VERSION 5.8 ;
BUSBITCHARS "[]" ;
DIVIDERCHAR "/" ;
UNITS
    DATABASE MICRONS 1000 ;
END UNITS

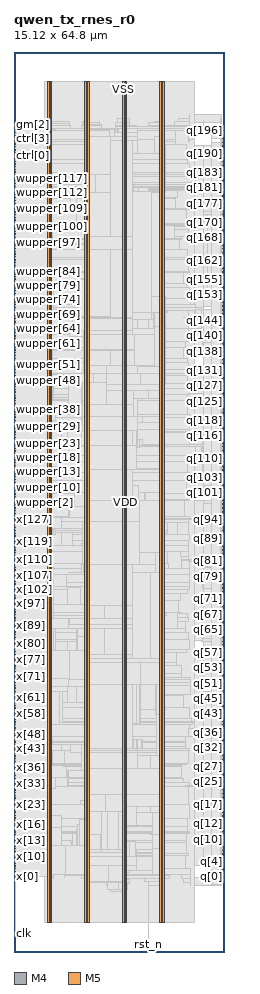
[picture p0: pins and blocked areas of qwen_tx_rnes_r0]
MACRO qwen_tx_rnes_r0
  FOREIGN qwen_tx_rnes_r0 0 0 ;
  CLASS BLOCK ;
  SIZE 15.12 BY 64.8 ;
  PIN clk
    DIRECTION INPUT ;
    USE SIGNAL ;
    PORT
      LAYER M4 ;
        RECT  0.054 1.296 0.138 1.32 ;
    END
    PORT
      LAYER M4 ;
        RECT  0.108 1.296 0.227 1.416 ;
    END
  END clk
  PIN ctrl[0]
    DIRECTION INPUT ;
    USE SIGNAL ;
    PORT
      LAYER M4 ;
        RECT  0.054 57.36 0.138 57.384 ;
    END
  END ctrl[0]
  PIN ctrl[1]
    DIRECTION INPUT ;
    USE SIGNAL ;
    PORT
      LAYER M4 ;
        RECT  0.054 57.552 0.138 57.576 ;
    END
  END ctrl[1]
  PIN ctrl[2]
    DIRECTION INPUT ;
    USE SIGNAL ;
    PORT
      LAYER M4 ;
        RECT  0.054 57.744 0.138 57.768 ;
    END
  END ctrl[2]
  PIN ctrl[3]
    DIRECTION INPUT ;
    USE SIGNAL ;
    PORT
      LAYER M4 ;
        RECT  0.054 57.984 0.138 58.008 ;
    END
  END ctrl[3]
  PIN ctrl[4]
    DIRECTION INPUT ;
    USE SIGNAL ;
    PORT
      LAYER M4 ;
        RECT  0.054 58.176 0.138 58.2 ;
    END
  END ctrl[4]
  PIN ctrl[5]
    DIRECTION INPUT ;
    USE SIGNAL ;
    PORT
      LAYER M4 ;
        RECT  0.054 58.368 0.138 58.392 ;
    END
  END ctrl[5]
  PIN gm[0]
    DIRECTION INPUT ;
    USE SIGNAL ;
    PORT
      LAYER M4 ;
        RECT  0.054 58.56 0.138 58.584 ;
    END
  END gm[0]
  PIN gm[1]
    DIRECTION INPUT ;
    USE SIGNAL ;
    PORT
      LAYER M4 ;
        RECT  0.054 58.8 0.138 58.824 ;
    END
  END gm[1]
  PIN gm[2]
    DIRECTION INPUT ;
    USE SIGNAL ;
    PORT
      LAYER M4 ;
        RECT  0.054 58.992 0.138 59.016 ;
    END
  END gm[2]
  PIN gm[3]
    DIRECTION INPUT ;
    USE SIGNAL ;
    PORT
      LAYER M4 ;
        RECT  0.054 59.184 0.138 59.208 ;
    END
  END gm[3]
  PIN q[0]
    DIRECTION OUTPUT ;
    USE SIGNAL ;
    PORT
      LAYER M4 ;
        RECT  14.982 5.424 15.066 5.448 ;
    END
  END q[0]
  PIN q[100]
    DIRECTION OUTPUT ;
    USE SIGNAL ;
    PORT
      LAYER M4 ;
        RECT  14.982 32.784 15.066 32.808 ;
    END
  END q[100]
  PIN q[101]
    DIRECTION OUTPUT ;
    USE SIGNAL ;
    PORT
      LAYER M4 ;
        RECT  14.982 33.072 15.066 33.096 ;
    END
  END q[101]
  PIN q[102]
    DIRECTION OUTPUT ;
    USE SIGNAL ;
    PORT
      LAYER M4 ;
        RECT  14.982 33.36 15.066 33.384 ;
    END
  END q[102]
  PIN q[103]
    DIRECTION OUTPUT ;
    USE SIGNAL ;
    PORT
      LAYER M4 ;
        RECT  14.982 33.6 15.066 33.624 ;
    END
  END q[103]
  PIN q[104]
    DIRECTION OUTPUT ;
    USE SIGNAL ;
    PORT
      LAYER M4 ;
        RECT  14.982 33.888 15.066 33.912 ;
    END
  END q[104]
  PIN q[105]
    DIRECTION OUTPUT ;
    USE SIGNAL ;
    PORT
      LAYER M4 ;
        RECT  14.982 34.176 15.066 34.2 ;
    END
  END q[105]
  PIN q[106]
    DIRECTION OUTPUT ;
    USE SIGNAL ;
    PORT
      LAYER M4 ;
        RECT  14.982 34.464 15.066 34.488 ;
    END
  END q[106]
  PIN q[107]
    DIRECTION OUTPUT ;
    USE SIGNAL ;
    PORT
      LAYER M4 ;
        RECT  14.982 34.704 15.066 34.728 ;
    END
  END q[107]
  PIN q[108]
    DIRECTION OUTPUT ;
    USE SIGNAL ;
    PORT
      LAYER M4 ;
        RECT  14.982 34.992 15.066 35.016 ;
    END
  END q[108]
  PIN q[109]
    DIRECTION OUTPUT ;
    USE SIGNAL ;
    PORT
      LAYER M4 ;
        RECT  14.982 35.28 15.066 35.304 ;
    END
  END q[109]
  PIN q[10]
    DIRECTION OUTPUT ;
    USE SIGNAL ;
    PORT
      LAYER M4 ;
        RECT  14.982 8.112 15.066 8.136 ;
    END
  END q[10]
  PIN q[110]
    DIRECTION OUTPUT ;
    USE SIGNAL ;
    PORT
      LAYER M4 ;
        RECT  14.982 35.52 15.066 35.544 ;
    END
  END q[110]
  PIN q[111]
    DIRECTION OUTPUT ;
    USE SIGNAL ;
    PORT
      LAYER M4 ;
        RECT  14.982 35.808 15.066 35.832 ;
    END
  END q[111]
  PIN q[112]
    DIRECTION OUTPUT ;
    USE SIGNAL ;
    PORT
      LAYER M4 ;
        RECT  14.982 36.096 15.066 36.12 ;
    END
  END q[112]
  PIN q[113]
    DIRECTION OUTPUT ;
    USE SIGNAL ;
    PORT
      LAYER M4 ;
        RECT  14.982 36.384 15.066 36.408 ;
    END
  END q[113]
  PIN q[114]
    DIRECTION OUTPUT ;
    USE SIGNAL ;
    PORT
      LAYER M4 ;
        RECT  14.982 36.624 15.066 36.648 ;
    END
  END q[114]
  PIN q[115]
    DIRECTION OUTPUT ;
    USE SIGNAL ;
    PORT
      LAYER M4 ;
        RECT  14.982 36.912 15.066 36.936 ;
    END
  END q[115]
  PIN q[116]
    DIRECTION OUTPUT ;
    USE SIGNAL ;
    PORT
      LAYER M4 ;
        RECT  14.982 37.2 15.066 37.224 ;
    END
  END q[116]
  PIN q[117]
    DIRECTION OUTPUT ;
    USE SIGNAL ;
    PORT
      LAYER M4 ;
        RECT  14.982 37.44 15.066 37.464 ;
    END
  END q[117]
  PIN q[118]
    DIRECTION OUTPUT ;
    USE SIGNAL ;
    PORT
      LAYER M4 ;
        RECT  14.982 37.728 15.066 37.752 ;
    END
  END q[118]
  PIN q[119]
    DIRECTION OUTPUT ;
    USE SIGNAL ;
    PORT
      LAYER M4 ;
        RECT  14.982 38.016 15.066 38.04 ;
    END
  END q[119]
  PIN q[11]
    DIRECTION OUTPUT ;
    USE SIGNAL ;
    PORT
      LAYER M4 ;
        RECT  14.982 8.4 15.066 8.424 ;
    END
  END q[11]
  PIN q[120]
    DIRECTION OUTPUT ;
    USE SIGNAL ;
    PORT
      LAYER M4 ;
        RECT  14.982 38.304 15.066 38.328 ;
    END
  END q[120]
  PIN q[121]
    DIRECTION OUTPUT ;
    USE SIGNAL ;
    PORT
      LAYER M4 ;
        RECT  14.982 38.544 15.066 38.568 ;
    END
  END q[121]
  PIN q[122]
    DIRECTION OUTPUT ;
    USE SIGNAL ;
    PORT
      LAYER M4 ;
        RECT  14.982 38.832 15.066 38.856 ;
    END
  END q[122]
  PIN q[123]
    DIRECTION OUTPUT ;
    USE SIGNAL ;
    PORT
      LAYER M4 ;
        RECT  14.982 39.12 15.066 39.144 ;
    END
  END q[123]
  PIN q[124]
    DIRECTION OUTPUT ;
    USE SIGNAL ;
    PORT
      LAYER M4 ;
        RECT  14.982 39.36 15.066 39.384 ;
    END
  END q[124]
  PIN q[125]
    DIRECTION OUTPUT ;
    USE SIGNAL ;
    PORT
      LAYER M4 ;
        RECT  14.982 39.648 15.066 39.672 ;
    END
  END q[125]
  PIN q[126]
    DIRECTION OUTPUT ;
    USE SIGNAL ;
    PORT
      LAYER M4 ;
        RECT  14.982 39.936 15.066 39.96 ;
    END
  END q[126]
  PIN q[127]
    DIRECTION OUTPUT ;
    USE SIGNAL ;
    PORT
      LAYER M4 ;
        RECT  14.982 40.224 15.066 40.248 ;
    END
  END q[127]
  PIN q[128]
    DIRECTION OUTPUT ;
    USE SIGNAL ;
    PORT
      LAYER M4 ;
        RECT  14.982 40.464 15.066 40.488 ;
    END
  END q[128]
  PIN q[129]
    DIRECTION OUTPUT ;
    USE SIGNAL ;
    PORT
      LAYER M4 ;
        RECT  14.982 40.752 15.066 40.776 ;
    END
  END q[129]
  PIN q[12]
    DIRECTION OUTPUT ;
    USE SIGNAL ;
    PORT
      LAYER M4 ;
        RECT  14.982 8.688 15.066 8.712 ;
    END
  END q[12]
  PIN q[130]
    DIRECTION OUTPUT ;
    USE SIGNAL ;
    PORT
      LAYER M4 ;
        RECT  14.982 41.04 15.066 41.064 ;
    END
  END q[130]
  PIN q[131]
    DIRECTION OUTPUT ;
    USE SIGNAL ;
    PORT
      LAYER M4 ;
        RECT  14.982 41.28 15.066 41.304 ;
    END
  END q[131]
  PIN q[132]
    DIRECTION OUTPUT ;
    USE SIGNAL ;
    PORT
      LAYER M4 ;
        RECT  14.982 41.568 15.066 41.592 ;
    END
  END q[132]
  PIN q[133]
    DIRECTION OUTPUT ;
    USE SIGNAL ;
    PORT
      LAYER M4 ;
        RECT  14.982 41.856 15.066 41.88 ;
    END
  END q[133]
  PIN q[134]
    DIRECTION OUTPUT ;
    USE SIGNAL ;
    PORT
      LAYER M4 ;
        RECT  14.982 42.096 15.066 42.12 ;
    END
  END q[134]
  PIN q[135]
    DIRECTION OUTPUT ;
    USE SIGNAL ;
    PORT
      LAYER M4 ;
        RECT  14.982 42.384 15.066 42.408 ;
    END
  END q[135]
  PIN q[136]
    DIRECTION OUTPUT ;
    USE SIGNAL ;
    PORT
      LAYER M4 ;
        RECT  14.982 42.672 15.066 42.696 ;
    END
  END q[136]
  PIN q[137]
    DIRECTION OUTPUT ;
    USE SIGNAL ;
    PORT
      LAYER M4 ;
        RECT  14.982 42.96 15.066 42.984 ;
    END
  END q[137]
  PIN q[138]
    DIRECTION OUTPUT ;
    USE SIGNAL ;
    PORT
      LAYER M4 ;
        RECT  14.982 43.2 15.066 43.224 ;
    END
  END q[138]
  PIN q[139]
    DIRECTION OUTPUT ;
    USE SIGNAL ;
    PORT
      LAYER M4 ;
        RECT  14.982 43.488 15.066 43.512 ;
    END
  END q[139]
  PIN q[13]
    DIRECTION OUTPUT ;
    USE SIGNAL ;
    PORT
      LAYER M4 ;
        RECT  14.982 8.928 15.066 8.952 ;
    END
  END q[13]
  PIN q[140]
    DIRECTION OUTPUT ;
    USE SIGNAL ;
    PORT
      LAYER M4 ;
        RECT  14.982 43.776 15.066 43.8 ;
    END
  END q[140]
  PIN q[141]
    DIRECTION OUTPUT ;
    USE SIGNAL ;
    PORT
      LAYER M4 ;
        RECT  14.982 44.016 15.066 44.04 ;
    END
  END q[141]
  PIN q[142]
    DIRECTION OUTPUT ;
    USE SIGNAL ;
    PORT
      LAYER M4 ;
        RECT  14.982 44.304 15.066 44.328 ;
    END
  END q[142]
  PIN q[143]
    DIRECTION OUTPUT ;
    USE SIGNAL ;
    PORT
      LAYER M4 ;
        RECT  14.982 44.592 15.066 44.616 ;
    END
  END q[143]
  PIN q[144]
    DIRECTION OUTPUT ;
    USE SIGNAL ;
    PORT
      LAYER M4 ;
        RECT  14.982 44.88 15.066 44.904 ;
    END
  END q[144]
  PIN q[145]
    DIRECTION OUTPUT ;
    USE SIGNAL ;
    PORT
      LAYER M4 ;
        RECT  14.982 45.12 15.066 45.144 ;
    END
  END q[145]
  PIN q[146]
    DIRECTION OUTPUT ;
    USE SIGNAL ;
    PORT
      LAYER M4 ;
        RECT  14.982 45.408 15.066 45.432 ;
    END
  END q[146]
  PIN q[147]
    DIRECTION OUTPUT ;
    USE SIGNAL ;
    PORT
      LAYER M4 ;
        RECT  14.982 45.696 15.066 45.72 ;
    END
  END q[147]
  PIN q[148]
    DIRECTION OUTPUT ;
    USE SIGNAL ;
    PORT
      LAYER M4 ;
        RECT  14.982 45.936 15.066 45.96 ;
    END
  END q[148]
  PIN q[149]
    DIRECTION OUTPUT ;
    USE SIGNAL ;
    PORT
      LAYER M4 ;
        RECT  14.982 46.224 15.066 46.248 ;
    END
  END q[149]
  PIN q[14]
    DIRECTION OUTPUT ;
    USE SIGNAL ;
    PORT
      LAYER M4 ;
        RECT  14.982 9.216 15.066 9.24 ;
    END
  END q[14]
  PIN q[150]
    DIRECTION OUTPUT ;
    USE SIGNAL ;
    PORT
      LAYER M4 ;
        RECT  14.982 46.512 15.066 46.536 ;
    END
  END q[150]
  PIN q[151]
    DIRECTION OUTPUT ;
    USE SIGNAL ;
    PORT
      LAYER M4 ;
        RECT  14.982 46.8 15.066 46.824 ;
    END
  END q[151]
  PIN q[152]
    DIRECTION OUTPUT ;
    USE SIGNAL ;
    PORT
      LAYER M4 ;
        RECT  14.982 47.04 15.066 47.064 ;
    END
  END q[152]
  PIN q[153]
    DIRECTION OUTPUT ;
    USE SIGNAL ;
    PORT
      LAYER M4 ;
        RECT  14.982 47.328 15.066 47.352 ;
    END
  END q[153]
  PIN q[154]
    DIRECTION OUTPUT ;
    USE SIGNAL ;
    PORT
      LAYER M4 ;
        RECT  14.982 47.616 15.066 47.64 ;
    END
  END q[154]
  PIN q[155]
    DIRECTION OUTPUT ;
    USE SIGNAL ;
    PORT
      LAYER M4 ;
        RECT  14.982 47.856 15.066 47.88 ;
    END
  END q[155]
  PIN q[156]
    DIRECTION OUTPUT ;
    USE SIGNAL ;
    PORT
      LAYER M4 ;
        RECT  14.982 48.144 15.066 48.168 ;
    END
  END q[156]
  PIN q[157]
    DIRECTION OUTPUT ;
    USE SIGNAL ;
    PORT
      LAYER M4 ;
        RECT  14.982 48.432 15.066 48.456 ;
    END
  END q[157]
  PIN q[158]
    DIRECTION OUTPUT ;
    USE SIGNAL ;
    PORT
      LAYER M4 ;
        RECT  14.982 48.72 15.066 48.744 ;
    END
  END q[158]
  PIN q[159]
    DIRECTION OUTPUT ;
    USE SIGNAL ;
    PORT
      LAYER M4 ;
        RECT  14.982 48.96 15.066 48.984 ;
    END
  END q[159]
  PIN q[15]
    DIRECTION OUTPUT ;
    USE SIGNAL ;
    PORT
      LAYER M4 ;
        RECT  14.982 9.504 15.066 9.528 ;
    END
  END q[15]
  PIN q[160]
    DIRECTION OUTPUT ;
    USE SIGNAL ;
    PORT
      LAYER M4 ;
        RECT  14.982 49.248 15.066 49.272 ;
    END
  END q[160]
  PIN q[161]
    DIRECTION OUTPUT ;
    USE SIGNAL ;
    PORT
      LAYER M4 ;
        RECT  14.982 49.536 15.066 49.56 ;
    END
  END q[161]
  PIN q[162]
    DIRECTION OUTPUT ;
    USE SIGNAL ;
    PORT
      LAYER M4 ;
        RECT  14.982 49.776 15.066 49.8 ;
    END
  END q[162]
  PIN q[163]
    DIRECTION OUTPUT ;
    USE SIGNAL ;
    PORT
      LAYER M4 ;
        RECT  14.982 50.064 15.066 50.088 ;
    END
  END q[163]
  PIN q[164]
    DIRECTION OUTPUT ;
    USE SIGNAL ;
    PORT
      LAYER M4 ;
        RECT  14.982 50.352 15.066 50.376 ;
    END
  END q[164]
  PIN q[165]
    DIRECTION OUTPUT ;
    USE SIGNAL ;
    PORT
      LAYER M4 ;
        RECT  14.982 50.64 15.066 50.664 ;
    END
  END q[165]
  PIN q[166]
    DIRECTION OUTPUT ;
    USE SIGNAL ;
    PORT
      LAYER M4 ;
        RECT  14.982 50.88 15.066 50.904 ;
    END
  END q[166]
  PIN q[167]
    DIRECTION OUTPUT ;
    USE SIGNAL ;
    PORT
      LAYER M4 ;
        RECT  14.982 51.168 15.066 51.192 ;
    END
  END q[167]
  PIN q[168]
    DIRECTION OUTPUT ;
    USE SIGNAL ;
    PORT
      LAYER M4 ;
        RECT  14.982 51.456 15.066 51.48 ;
    END
  END q[168]
  PIN q[169]
    DIRECTION OUTPUT ;
    USE SIGNAL ;
    PORT
      LAYER M4 ;
        RECT  14.982 51.696 15.066 51.72 ;
    END
  END q[169]
  PIN q[16]
    DIRECTION OUTPUT ;
    USE SIGNAL ;
    PORT
      LAYER M4 ;
        RECT  14.982 9.792 15.066 9.816 ;
    END
  END q[16]
  PIN q[170]
    DIRECTION OUTPUT ;
    USE SIGNAL ;
    PORT
      LAYER M4 ;
        RECT  14.982 51.984 15.066 52.008 ;
    END
  END q[170]
  PIN q[171]
    DIRECTION OUTPUT ;
    USE SIGNAL ;
    PORT
      LAYER M4 ;
        RECT  14.982 52.272 15.066 52.296 ;
    END
  END q[171]
  PIN q[172]
    DIRECTION OUTPUT ;
    USE SIGNAL ;
    PORT
      LAYER M4 ;
        RECT  14.982 52.512 15.066 52.536 ;
    END
  END q[172]
  PIN q[173]
    DIRECTION OUTPUT ;
    USE SIGNAL ;
    PORT
      LAYER M4 ;
        RECT  14.982 52.8 15.066 52.824 ;
    END
  END q[173]
  PIN q[174]
    DIRECTION OUTPUT ;
    USE SIGNAL ;
    PORT
      LAYER M4 ;
        RECT  14.982 53.088 15.066 53.112 ;
    END
  END q[174]
  PIN q[175]
    DIRECTION OUTPUT ;
    USE SIGNAL ;
    PORT
      LAYER M4 ;
        RECT  14.982 53.376 15.066 53.4 ;
    END
  END q[175]
  PIN q[176]
    DIRECTION OUTPUT ;
    USE SIGNAL ;
    PORT
      LAYER M4 ;
        RECT  14.982 53.616 15.066 53.64 ;
    END
  END q[176]
  PIN q[177]
    DIRECTION OUTPUT ;
    USE SIGNAL ;
    PORT
      LAYER M4 ;
        RECT  14.982 53.904 15.066 53.928 ;
    END
  END q[177]
  PIN q[178]
    DIRECTION OUTPUT ;
    USE SIGNAL ;
    PORT
      LAYER M4 ;
        RECT  14.982 54.192 15.066 54.216 ;
    END
  END q[178]
  PIN q[179]
    DIRECTION OUTPUT ;
    USE SIGNAL ;
    PORT
      LAYER M4 ;
        RECT  14.982 54.432 15.066 54.456 ;
    END
  END q[179]
  PIN q[17]
    DIRECTION OUTPUT ;
    USE SIGNAL ;
    PORT
      LAYER M4 ;
        RECT  14.982 10.032 15.066 10.056 ;
    END
  END q[17]
  PIN q[180]
    DIRECTION OUTPUT ;
    USE SIGNAL ;
    PORT
      LAYER M4 ;
        RECT  14.982 54.72 15.066 54.744 ;
    END
  END q[180]
  PIN q[181]
    DIRECTION OUTPUT ;
    USE SIGNAL ;
    PORT
      LAYER M4 ;
        RECT  14.982 55.008 15.066 55.032 ;
    END
  END q[181]
  PIN q[182]
    DIRECTION OUTPUT ;
    USE SIGNAL ;
    PORT
      LAYER M4 ;
        RECT  14.982 55.296 15.066 55.32 ;
    END
  END q[182]
  PIN q[183]
    DIRECTION OUTPUT ;
    USE SIGNAL ;
    PORT
      LAYER M4 ;
        RECT  14.982 55.536 15.066 55.56 ;
    END
  END q[183]
  PIN q[184]
    DIRECTION OUTPUT ;
    USE SIGNAL ;
    PORT
      LAYER M4 ;
        RECT  14.982 55.824 15.066 55.848 ;
    END
  END q[184]
  PIN q[185]
    DIRECTION OUTPUT ;
    USE SIGNAL ;
    PORT
      LAYER M4 ;
        RECT  14.982 56.112 15.066 56.136 ;
    END
  END q[185]
  PIN q[186]
    DIRECTION OUTPUT ;
    USE SIGNAL ;
    PORT
      LAYER M4 ;
        RECT  14.982 56.352 15.066 56.376 ;
    END
  END q[186]
  PIN q[187]
    DIRECTION OUTPUT ;
    USE SIGNAL ;
    PORT
      LAYER M4 ;
        RECT  14.982 56.64 15.066 56.664 ;
    END
  END q[187]
  PIN q[188]
    DIRECTION OUTPUT ;
    USE SIGNAL ;
    PORT
      LAYER M4 ;
        RECT  14.982 56.928 15.066 56.952 ;
    END
  END q[188]
  PIN q[189]
    DIRECTION OUTPUT ;
    USE SIGNAL ;
    PORT
      LAYER M4 ;
        RECT  14.982 57.216 15.066 57.24 ;
    END
  END q[189]
  PIN q[18]
    DIRECTION OUTPUT ;
    USE SIGNAL ;
    PORT
      LAYER M4 ;
        RECT  14.982 10.32 15.066 10.344 ;
    END
  END q[18]
  PIN q[190]
    DIRECTION OUTPUT ;
    USE SIGNAL ;
    PORT
      LAYER M4 ;
        RECT  14.982 57.456 15.066 57.48 ;
    END
  END q[190]
  PIN q[191]
    DIRECTION OUTPUT ;
    USE SIGNAL ;
    PORT
      LAYER M4 ;
        RECT  14.982 57.744 15.066 57.768 ;
    END
  END q[191]
  PIN q[192]
    DIRECTION OUTPUT ;
    USE SIGNAL ;
    PORT
      LAYER M4 ;
        RECT  14.982 58.032 15.066 58.056 ;
    END
  END q[192]
  PIN q[193]
    DIRECTION OUTPUT ;
    USE SIGNAL ;
    PORT
      LAYER M4 ;
        RECT  14.982 58.272 15.066 58.296 ;
    END
  END q[193]
  PIN q[194]
    DIRECTION OUTPUT ;
    USE SIGNAL ;
    PORT
      LAYER M4 ;
        RECT  14.982 58.56 15.066 58.584 ;
    END
  END q[194]
  PIN q[195]
    DIRECTION OUTPUT ;
    USE SIGNAL ;
    PORT
      LAYER M4 ;
        RECT  14.982 58.848 15.066 58.872 ;
    END
  END q[195]
  PIN q[196]
    DIRECTION OUTPUT ;
    USE SIGNAL ;
    PORT
      LAYER M4 ;
        RECT  14.982 59.136 15.066 59.16 ;
    END
  END q[196]
  PIN q[197]
    DIRECTION OUTPUT ;
    USE SIGNAL ;
    PORT
      LAYER M4 ;
        RECT  14.982 59.376 15.066 59.4 ;
    END
  END q[197]
  PIN q[19]
    DIRECTION OUTPUT ;
    USE SIGNAL ;
    PORT
      LAYER M4 ;
        RECT  14.982 10.608 15.066 10.632 ;
    END
  END q[19]
  PIN q[1]
    DIRECTION OUTPUT ;
    USE SIGNAL ;
    PORT
      LAYER M4 ;
        RECT  14.982 5.664 15.066 5.688 ;
    END
  END q[1]
  PIN q[20]
    DIRECTION OUTPUT ;
    USE SIGNAL ;
    PORT
      LAYER M4 ;
        RECT  14.982 10.848 15.066 10.872 ;
    END
  END q[20]
  PIN q[21]
    DIRECTION OUTPUT ;
    USE SIGNAL ;
    PORT
      LAYER M4 ;
        RECT  14.982 11.136 15.066 11.16 ;
    END
  END q[21]
  PIN q[22]
    DIRECTION OUTPUT ;
    USE SIGNAL ;
    PORT
      LAYER M4 ;
        RECT  14.982 11.424 15.066 11.448 ;
    END
  END q[22]
  PIN q[23]
    DIRECTION OUTPUT ;
    USE SIGNAL ;
    PORT
      LAYER M4 ;
        RECT  14.982 11.712 15.066 11.736 ;
    END
  END q[23]
  PIN q[24]
    DIRECTION OUTPUT ;
    USE SIGNAL ;
    PORT
      LAYER M4 ;
        RECT  14.982 11.952 15.066 11.976 ;
    END
  END q[24]
  PIN q[25]
    DIRECTION OUTPUT ;
    USE SIGNAL ;
    PORT
      LAYER M4 ;
        RECT  14.982 12.24 15.066 12.264 ;
    END
  END q[25]
  PIN q[26]
    DIRECTION OUTPUT ;
    USE SIGNAL ;
    PORT
      LAYER M4 ;
        RECT  14.982 12.528 15.066 12.552 ;
    END
  END q[26]
  PIN q[27]
    DIRECTION OUTPUT ;
    USE SIGNAL ;
    PORT
      LAYER M4 ;
        RECT  14.982 12.768 15.066 12.792 ;
    END
  END q[27]
  PIN q[28]
    DIRECTION OUTPUT ;
    USE SIGNAL ;
    PORT
      LAYER M4 ;
        RECT  14.982 13.056 15.066 13.08 ;
    END
  END q[28]
  PIN q[29]
    DIRECTION OUTPUT ;
    USE SIGNAL ;
    PORT
      LAYER M4 ;
        RECT  14.982 13.344 15.066 13.368 ;
    END
  END q[29]
  PIN q[2]
    DIRECTION OUTPUT ;
    USE SIGNAL ;
    PORT
      LAYER M4 ;
        RECT  14.982 5.952 15.066 5.976 ;
    END
  END q[2]
  PIN q[30]
    DIRECTION OUTPUT ;
    USE SIGNAL ;
    PORT
      LAYER M4 ;
        RECT  14.982 13.632 15.066 13.656 ;
    END
  END q[30]
  PIN q[31]
    DIRECTION OUTPUT ;
    USE SIGNAL ;
    PORT
      LAYER M4 ;
        RECT  14.982 13.872 15.066 13.896 ;
    END
  END q[31]
  PIN q[32]
    DIRECTION OUTPUT ;
    USE SIGNAL ;
    PORT
      LAYER M4 ;
        RECT  14.982 14.16 15.066 14.184 ;
    END
  END q[32]
  PIN q[33]
    DIRECTION OUTPUT ;
    USE SIGNAL ;
    PORT
      LAYER M4 ;
        RECT  14.982 14.448 15.066 14.472 ;
    END
  END q[33]
  PIN q[34]
    DIRECTION OUTPUT ;
    USE SIGNAL ;
    PORT
      LAYER M4 ;
        RECT  14.982 14.688 15.066 14.712 ;
    END
  END q[34]
  PIN q[35]
    DIRECTION OUTPUT ;
    USE SIGNAL ;
    PORT
      LAYER M4 ;
        RECT  14.982 14.976 15.066 15 ;
    END
  END q[35]
  PIN q[36]
    DIRECTION OUTPUT ;
    USE SIGNAL ;
    PORT
      LAYER M4 ;
        RECT  14.982 15.264 15.066 15.288 ;
    END
  END q[36]
  PIN q[37]
    DIRECTION OUTPUT ;
    USE SIGNAL ;
    PORT
      LAYER M4 ;
        RECT  14.982 15.552 15.066 15.576 ;
    END
  END q[37]
  PIN q[38]
    DIRECTION OUTPUT ;
    USE SIGNAL ;
    PORT
      LAYER M4 ;
        RECT  14.982 15.792 15.066 15.816 ;
    END
  END q[38]
  PIN q[39]
    DIRECTION OUTPUT ;
    USE SIGNAL ;
    PORT
      LAYER M4 ;
        RECT  14.982 16.08 15.066 16.104 ;
    END
  END q[39]
  PIN q[3]
    DIRECTION OUTPUT ;
    USE SIGNAL ;
    PORT
      LAYER M4 ;
        RECT  14.982 6.192 15.066 6.216 ;
    END
  END q[3]
  PIN q[40]
    DIRECTION OUTPUT ;
    USE SIGNAL ;
    PORT
      LAYER M4 ;
        RECT  14.982 16.368 15.066 16.392 ;
    END
  END q[40]
  PIN q[41]
    DIRECTION OUTPUT ;
    USE SIGNAL ;
    PORT
      LAYER M4 ;
        RECT  14.982 16.608 15.066 16.632 ;
    END
  END q[41]
  PIN q[42]
    DIRECTION OUTPUT ;
    USE SIGNAL ;
    PORT
      LAYER M4 ;
        RECT  14.982 16.896 15.066 16.92 ;
    END
  END q[42]
  PIN q[43]
    DIRECTION OUTPUT ;
    USE SIGNAL ;
    PORT
      LAYER M4 ;
        RECT  14.982 17.184 15.066 17.208 ;
    END
  END q[43]
  PIN q[44]
    DIRECTION OUTPUT ;
    USE SIGNAL ;
    PORT
      LAYER M4 ;
        RECT  14.982 17.472 15.066 17.496 ;
    END
  END q[44]
  PIN q[45]
    DIRECTION OUTPUT ;
    USE SIGNAL ;
    PORT
      LAYER M4 ;
        RECT  14.982 17.712 15.066 17.736 ;
    END
  END q[45]
  PIN q[46]
    DIRECTION OUTPUT ;
    USE SIGNAL ;
    PORT
      LAYER M4 ;
        RECT  14.982 18 15.066 18.024 ;
    END
  END q[46]
  PIN q[47]
    DIRECTION OUTPUT ;
    USE SIGNAL ;
    PORT
      LAYER M4 ;
        RECT  14.982 18.288 15.066 18.312 ;
    END
  END q[47]
  PIN q[48]
    DIRECTION OUTPUT ;
    USE SIGNAL ;
    PORT
      LAYER M4 ;
        RECT  14.982 18.528 15.066 18.552 ;
    END
  END q[48]
  PIN q[49]
    DIRECTION OUTPUT ;
    USE SIGNAL ;
    PORT
      LAYER M4 ;
        RECT  14.982 18.816 15.066 18.84 ;
    END
  END q[49]
  PIN q[4]
    DIRECTION OUTPUT ;
    USE SIGNAL ;
    PORT
      LAYER M4 ;
        RECT  14.982 6.48 15.066 6.504 ;
    END
  END q[4]
  PIN q[50]
    DIRECTION OUTPUT ;
    USE SIGNAL ;
    PORT
      LAYER M4 ;
        RECT  14.982 19.104 15.066 19.128 ;
    END
  END q[50]
  PIN q[51]
    DIRECTION OUTPUT ;
    USE SIGNAL ;
    PORT
      LAYER M4 ;
        RECT  14.982 19.344 15.066 19.368 ;
    END
  END q[51]
  PIN q[52]
    DIRECTION OUTPUT ;
    USE SIGNAL ;
    PORT
      LAYER M4 ;
        RECT  14.982 19.632 15.066 19.656 ;
    END
  END q[52]
  PIN q[53]
    DIRECTION OUTPUT ;
    USE SIGNAL ;
    PORT
      LAYER M4 ;
        RECT  14.982 19.92 15.066 19.944 ;
    END
  END q[53]
  PIN q[54]
    DIRECTION OUTPUT ;
    USE SIGNAL ;
    PORT
      LAYER M4 ;
        RECT  14.982 20.208 15.066 20.232 ;
    END
  END q[54]
  PIN q[55]
    DIRECTION OUTPUT ;
    USE SIGNAL ;
    PORT
      LAYER M4 ;
        RECT  14.982 20.448 15.066 20.472 ;
    END
  END q[55]
  PIN q[56]
    DIRECTION OUTPUT ;
    USE SIGNAL ;
    PORT
      LAYER M4 ;
        RECT  14.982 20.736 15.066 20.76 ;
    END
  END q[56]
  PIN q[57]
    DIRECTION OUTPUT ;
    USE SIGNAL ;
    PORT
      LAYER M4 ;
        RECT  14.982 21.024 15.066 21.048 ;
    END
  END q[57]
  PIN q[58]
    DIRECTION OUTPUT ;
    USE SIGNAL ;
    PORT
      LAYER M4 ;
        RECT  14.982 21.264 15.066 21.288 ;
    END
  END q[58]
  PIN q[59]
    DIRECTION OUTPUT ;
    USE SIGNAL ;
    PORT
      LAYER M4 ;
        RECT  14.982 21.552 15.066 21.576 ;
    END
  END q[59]
  PIN q[5]
    DIRECTION OUTPUT ;
    USE SIGNAL ;
    PORT
      LAYER M4 ;
        RECT  14.982 6.768 15.066 6.792 ;
    END
  END q[5]
  PIN q[60]
    DIRECTION OUTPUT ;
    USE SIGNAL ;
    PORT
      LAYER M4 ;
        RECT  14.982 21.84 15.066 21.864 ;
    END
  END q[60]
  PIN q[61]
    DIRECTION OUTPUT ;
    USE SIGNAL ;
    PORT
      LAYER M4 ;
        RECT  14.982 22.128 15.066 22.152 ;
    END
  END q[61]
  PIN q[62]
    DIRECTION OUTPUT ;
    USE SIGNAL ;
    PORT
      LAYER M4 ;
        RECT  14.982 22.368 15.066 22.392 ;
    END
  END q[62]
  PIN q[63]
    DIRECTION OUTPUT ;
    USE SIGNAL ;
    PORT
      LAYER M4 ;
        RECT  14.982 22.656 15.066 22.68 ;
    END
  END q[63]
  PIN q[64]
    DIRECTION OUTPUT ;
    USE SIGNAL ;
    PORT
      LAYER M4 ;
        RECT  14.982 22.944 15.066 22.968 ;
    END
  END q[64]
  PIN q[65]
    DIRECTION OUTPUT ;
    USE SIGNAL ;
    PORT
      LAYER M4 ;
        RECT  14.982 23.184 15.066 23.208 ;
    END
  END q[65]
  PIN q[66]
    DIRECTION OUTPUT ;
    USE SIGNAL ;
    PORT
      LAYER M4 ;
        RECT  14.982 23.472 15.066 23.496 ;
    END
  END q[66]
  PIN q[67]
    DIRECTION OUTPUT ;
    USE SIGNAL ;
    PORT
      LAYER M4 ;
        RECT  14.982 23.76 15.066 23.784 ;
    END
  END q[67]
  PIN q[68]
    DIRECTION OUTPUT ;
    USE SIGNAL ;
    PORT
      LAYER M4 ;
        RECT  14.982 24.048 15.066 24.072 ;
    END
  END q[68]
  PIN q[69]
    DIRECTION OUTPUT ;
    USE SIGNAL ;
    PORT
      LAYER M4 ;
        RECT  14.982 24.288 15.066 24.312 ;
    END
  END q[69]
  PIN q[6]
    DIRECTION OUTPUT ;
    USE SIGNAL ;
    PORT
      LAYER M4 ;
        RECT  14.982 7.056 15.066 7.08 ;
    END
  END q[6]
  PIN q[70]
    DIRECTION OUTPUT ;
    USE SIGNAL ;
    PORT
      LAYER M4 ;
        RECT  14.982 24.576 15.066 24.6 ;
    END
  END q[70]
  PIN q[71]
    DIRECTION OUTPUT ;
    USE SIGNAL ;
    PORT
      LAYER M4 ;
        RECT  14.982 24.864 15.066 24.888 ;
    END
  END q[71]
  PIN q[72]
    DIRECTION OUTPUT ;
    USE SIGNAL ;
    PORT
      LAYER M4 ;
        RECT  14.982 25.104 15.066 25.128 ;
    END
  END q[72]
  PIN q[73]
    DIRECTION OUTPUT ;
    USE SIGNAL ;
    PORT
      LAYER M4 ;
        RECT  14.982 25.392 15.066 25.416 ;
    END
  END q[73]
  PIN q[74]
    DIRECTION OUTPUT ;
    USE SIGNAL ;
    PORT
      LAYER M4 ;
        RECT  14.982 25.68 15.066 25.704 ;
    END
  END q[74]
  PIN q[75]
    DIRECTION OUTPUT ;
    USE SIGNAL ;
    PORT
      LAYER M4 ;
        RECT  14.982 25.968 15.066 25.992 ;
    END
  END q[75]
  PIN q[76]
    DIRECTION OUTPUT ;
    USE SIGNAL ;
    PORT
      LAYER M4 ;
        RECT  14.982 26.208 15.066 26.232 ;
    END
  END q[76]
  PIN q[77]
    DIRECTION OUTPUT ;
    USE SIGNAL ;
    PORT
      LAYER M4 ;
        RECT  14.982 26.496 15.066 26.52 ;
    END
  END q[77]
  PIN q[78]
    DIRECTION OUTPUT ;
    USE SIGNAL ;
    PORT
      LAYER M4 ;
        RECT  14.982 26.784 15.066 26.808 ;
    END
  END q[78]
  PIN q[79]
    DIRECTION OUTPUT ;
    USE SIGNAL ;
    PORT
      LAYER M4 ;
        RECT  14.982 27.024 15.066 27.048 ;
    END
  END q[79]
  PIN q[7]
    DIRECTION OUTPUT ;
    USE SIGNAL ;
    PORT
      LAYER M4 ;
        RECT  14.982 7.296 15.066 7.32 ;
    END
  END q[7]
  PIN q[80]
    DIRECTION OUTPUT ;
    USE SIGNAL ;
    PORT
      LAYER M4 ;
        RECT  14.982 27.312 15.066 27.336 ;
    END
  END q[80]
  PIN q[81]
    DIRECTION OUTPUT ;
    USE SIGNAL ;
    PORT
      LAYER M4 ;
        RECT  14.982 27.6 15.066 27.624 ;
    END
  END q[81]
  PIN q[82]
    DIRECTION OUTPUT ;
    USE SIGNAL ;
    PORT
      LAYER M4 ;
        RECT  14.982 27.888 15.066 27.912 ;
    END
  END q[82]
  PIN q[83]
    DIRECTION OUTPUT ;
    USE SIGNAL ;
    PORT
      LAYER M4 ;
        RECT  14.982 28.128 15.066 28.152 ;
    END
  END q[83]
  PIN q[84]
    DIRECTION OUTPUT ;
    USE SIGNAL ;
    PORT
      LAYER M4 ;
        RECT  14.982 28.416 15.066 28.44 ;
    END
  END q[84]
  PIN q[85]
    DIRECTION OUTPUT ;
    USE SIGNAL ;
    PORT
      LAYER M4 ;
        RECT  14.982 28.704 15.066 28.728 ;
    END
  END q[85]
  PIN q[86]
    DIRECTION OUTPUT ;
    USE SIGNAL ;
    PORT
      LAYER M4 ;
        RECT  14.982 28.944 15.066 28.968 ;
    END
  END q[86]
  PIN q[87]
    DIRECTION OUTPUT ;
    USE SIGNAL ;
    PORT
      LAYER M4 ;
        RECT  14.982 29.232 15.066 29.256 ;
    END
  END q[87]
  PIN q[88]
    DIRECTION OUTPUT ;
    USE SIGNAL ;
    PORT
      LAYER M4 ;
        RECT  14.982 29.52 15.066 29.544 ;
    END
  END q[88]
  PIN q[89]
    DIRECTION OUTPUT ;
    USE SIGNAL ;
    PORT
      LAYER M4 ;
        RECT  14.982 29.76 15.066 29.784 ;
    END
  END q[89]
  PIN q[8]
    DIRECTION OUTPUT ;
    USE SIGNAL ;
    PORT
      LAYER M4 ;
        RECT  14.982 7.584 15.066 7.608 ;
    END
  END q[8]
  PIN q[90]
    DIRECTION OUTPUT ;
    USE SIGNAL ;
    PORT
      LAYER M4 ;
        RECT  14.982 30.048 15.066 30.072 ;
    END
  END q[90]
  PIN q[91]
    DIRECTION OUTPUT ;
    USE SIGNAL ;
    PORT
      LAYER M4 ;
        RECT  14.982 30.336 15.066 30.36 ;
    END
  END q[91]
  PIN q[92]
    DIRECTION OUTPUT ;
    USE SIGNAL ;
    PORT
      LAYER M4 ;
        RECT  14.982 30.624 15.066 30.648 ;
    END
  END q[92]
  PIN q[93]
    DIRECTION OUTPUT ;
    USE SIGNAL ;
    PORT
      LAYER M4 ;
        RECT  14.982 30.864 15.066 30.888 ;
    END
  END q[93]
  PIN q[94]
    DIRECTION OUTPUT ;
    USE SIGNAL ;
    PORT
      LAYER M4 ;
        RECT  14.982 31.152 15.066 31.176 ;
    END
  END q[94]
  PIN q[95]
    DIRECTION OUTPUT ;
    USE SIGNAL ;
    PORT
      LAYER M4 ;
        RECT  14.982 31.44 15.066 31.464 ;
    END
  END q[95]
  PIN q[96]
    DIRECTION OUTPUT ;
    USE SIGNAL ;
    PORT
      LAYER M4 ;
        RECT  14.982 31.68 15.066 31.704 ;
    END
  END q[96]
  PIN q[97]
    DIRECTION OUTPUT ;
    USE SIGNAL ;
    PORT
      LAYER M4 ;
        RECT  14.982 31.968 15.066 31.992 ;
    END
  END q[97]
  PIN q[98]
    DIRECTION OUTPUT ;
    USE SIGNAL ;
    PORT
      LAYER M4 ;
        RECT  14.982 32.256 15.066 32.28 ;
    END
  END q[98]
  PIN q[99]
    DIRECTION OUTPUT ;
    USE SIGNAL ;
    PORT
      LAYER M4 ;
        RECT  14.982 32.544 15.066 32.568 ;
    END
  END q[99]
  PIN q[9]
    DIRECTION OUTPUT ;
    USE SIGNAL ;
    PORT
      LAYER M4 ;
        RECT  14.982 7.872 15.066 7.896 ;
    END
  END q[9]
  PIN round
    DIRECTION INPUT ;
    USE SIGNAL ;
    PORT
      LAYER M4 ;
        RECT  0.054 59.376 0.138 59.4 ;
    END
  END round
  PIN rst_n
    DIRECTION INPUT ;
    USE SIGNAL ;
    PORT
      LAYER M5 ;
        RECT  9.696 0.054 9.72 0.138 ;
    END
    PORT
      LAYER M5 ;
        RECT  9.696 0.08 9.72 0.563 ;
    END
  END rst_n
  PIN wupper[0]
    DIRECTION INPUT ;
    USE SIGNAL ;
    PORT
      LAYER M4 ;
        RECT  0.054 31.392 0.138 31.416 ;
    END
  END wupper[0]
  PIN wupper[100]
    DIRECTION INPUT ;
    USE SIGNAL ;
    PORT
      LAYER M4 ;
        RECT  0.054 51.696 0.138 51.72 ;
    END
  END wupper[100]
  PIN wupper[101]
    DIRECTION INPUT ;
    USE SIGNAL ;
    PORT
      LAYER M4 ;
        RECT  0.054 51.888 0.138 51.912 ;
    END
  END wupper[101]
  PIN wupper[102]
    DIRECTION INPUT ;
    USE SIGNAL ;
    PORT
      LAYER M4 ;
        RECT  0.054 52.08 0.138 52.104 ;
    END
  END wupper[102]
  PIN wupper[103]
    DIRECTION INPUT ;
    USE SIGNAL ;
    PORT
      LAYER M4 ;
        RECT  0.054 52.272 0.138 52.296 ;
    END
  END wupper[103]
  PIN wupper[104]
    DIRECTION INPUT ;
    USE SIGNAL ;
    PORT
      LAYER M4 ;
        RECT  0.054 52.464 0.138 52.488 ;
    END
  END wupper[104]
  PIN wupper[105]
    DIRECTION INPUT ;
    USE SIGNAL ;
    PORT
      LAYER M4 ;
        RECT  0.054 52.704 0.138 52.728 ;
    END
  END wupper[105]
  PIN wupper[106]
    DIRECTION INPUT ;
    USE SIGNAL ;
    PORT
      LAYER M4 ;
        RECT  0.054 52.896 0.138 52.92 ;
    END
  END wupper[106]
  PIN wupper[107]
    DIRECTION INPUT ;
    USE SIGNAL ;
    PORT
      LAYER M4 ;
        RECT  0.054 53.088 0.138 53.112 ;
    END
  END wupper[107]
  PIN wupper[108]
    DIRECTION INPUT ;
    USE SIGNAL ;
    PORT
      LAYER M4 ;
        RECT  0.054 53.28 0.138 53.304 ;
    END
  END wupper[108]
  PIN wupper[109]
    DIRECTION INPUT ;
    USE SIGNAL ;
    PORT
      LAYER M4 ;
        RECT  0.054 53.52 0.138 53.544 ;
    END
  END wupper[109]
  PIN wupper[10]
    DIRECTION INPUT ;
    USE SIGNAL ;
    PORT
      LAYER M4 ;
        RECT  0.054 33.408 0.138 33.432 ;
    END
  END wupper[10]
  PIN wupper[110]
    DIRECTION INPUT ;
    USE SIGNAL ;
    PORT
      LAYER M4 ;
        RECT  0.054 53.712 0.138 53.736 ;
    END
  END wupper[110]
  PIN wupper[111]
    DIRECTION INPUT ;
    USE SIGNAL ;
    PORT
      LAYER M4 ;
        RECT  0.054 53.904 0.138 53.928 ;
    END
  END wupper[111]
  PIN wupper[112]
    DIRECTION INPUT ;
    USE SIGNAL ;
    PORT
      LAYER M4 ;
        RECT  0.054 54.096 0.138 54.12 ;
    END
  END wupper[112]
  PIN wupper[113]
    DIRECTION INPUT ;
    USE SIGNAL ;
    PORT
      LAYER M4 ;
        RECT  0.054 54.336 0.138 54.36 ;
    END
  END wupper[113]
  PIN wupper[114]
    DIRECTION INPUT ;
    USE SIGNAL ;
    PORT
      LAYER M4 ;
        RECT  0.054 54.528 0.138 54.552 ;
    END
  END wupper[114]
  PIN wupper[115]
    DIRECTION INPUT ;
    USE SIGNAL ;
    PORT
      LAYER M4 ;
        RECT  0.054 54.72 0.138 54.744 ;
    END
  END wupper[115]
  PIN wupper[116]
    DIRECTION INPUT ;
    USE SIGNAL ;
    PORT
      LAYER M4 ;
        RECT  0.054 54.912 0.138 54.936 ;
    END
  END wupper[116]
  PIN wupper[117]
    DIRECTION INPUT ;
    USE SIGNAL ;
    PORT
      LAYER M4 ;
        RECT  0.054 55.104 0.138 55.128 ;
    END
  END wupper[117]
  PIN wupper[118]
    DIRECTION INPUT ;
    USE SIGNAL ;
    PORT
      LAYER M4 ;
        RECT  0.054 55.344 0.138 55.368 ;
    END
  END wupper[118]
  PIN wupper[119]
    DIRECTION INPUT ;
    USE SIGNAL ;
    PORT
      LAYER M4 ;
        RECT  0.054 55.536 0.138 55.56 ;
    END
  END wupper[119]
  PIN wupper[11]
    DIRECTION INPUT ;
    USE SIGNAL ;
    PORT
      LAYER M4 ;
        RECT  0.054 33.6 0.138 33.624 ;
    END
  END wupper[11]
  PIN wupper[120]
    DIRECTION INPUT ;
    USE SIGNAL ;
    PORT
      LAYER M4 ;
        RECT  0.054 55.728 0.138 55.752 ;
    END
  END wupper[120]
  PIN wupper[121]
    DIRECTION INPUT ;
    USE SIGNAL ;
    PORT
      LAYER M4 ;
        RECT  0.054 55.92 0.138 55.944 ;
    END
  END wupper[121]
  PIN wupper[122]
    DIRECTION INPUT ;
    USE SIGNAL ;
    PORT
      LAYER M4 ;
        RECT  0.054 56.16 0.138 56.184 ;
    END
  END wupper[122]
  PIN wupper[123]
    DIRECTION INPUT ;
    USE SIGNAL ;
    PORT
      LAYER M4 ;
        RECT  0.054 56.352 0.138 56.376 ;
    END
  END wupper[123]
  PIN wupper[124]
    DIRECTION INPUT ;
    USE SIGNAL ;
    PORT
      LAYER M4 ;
        RECT  0.054 56.544 0.138 56.568 ;
    END
  END wupper[124]
  PIN wupper[125]
    DIRECTION INPUT ;
    USE SIGNAL ;
    PORT
      LAYER M4 ;
        RECT  0.054 56.736 0.138 56.76 ;
    END
  END wupper[125]
  PIN wupper[126]
    DIRECTION INPUT ;
    USE SIGNAL ;
    PORT
      LAYER M4 ;
        RECT  0.054 56.928 0.138 56.952 ;
    END
  END wupper[126]
  PIN wupper[127]
    DIRECTION INPUT ;
    USE SIGNAL ;
    PORT
      LAYER M4 ;
        RECT  0.054 57.168 0.138 57.192 ;
    END
  END wupper[127]
  PIN wupper[12]
    DIRECTION INPUT ;
    USE SIGNAL ;
    PORT
      LAYER M4 ;
        RECT  0.054 33.792 0.138 33.816 ;
    END
  END wupper[12]
  PIN wupper[13]
    DIRECTION INPUT ;
    USE SIGNAL ;
    PORT
      LAYER M4 ;
        RECT  0.054 34.032 0.138 34.056 ;
    END
  END wupper[13]
  PIN wupper[14]
    DIRECTION INPUT ;
    USE SIGNAL ;
    PORT
      LAYER M4 ;
        RECT  0.054 34.224 0.138 34.248 ;
    END
  END wupper[14]
  PIN wupper[15]
    DIRECTION INPUT ;
    USE SIGNAL ;
    PORT
      LAYER M4 ;
        RECT  0.054 34.416 0.138 34.44 ;
    END
  END wupper[15]
  PIN wupper[16]
    DIRECTION INPUT ;
    USE SIGNAL ;
    PORT
      LAYER M4 ;
        RECT  0.054 34.608 0.138 34.632 ;
    END
  END wupper[16]
  PIN wupper[17]
    DIRECTION INPUT ;
    USE SIGNAL ;
    PORT
      LAYER M4 ;
        RECT  0.054 34.848 0.138 34.872 ;
    END
  END wupper[17]
  PIN wupper[18]
    DIRECTION INPUT ;
    USE SIGNAL ;
    PORT
      LAYER M4 ;
        RECT  0.054 35.04 0.138 35.064 ;
    END
  END wupper[18]
  PIN wupper[19]
    DIRECTION INPUT ;
    USE SIGNAL ;
    PORT
      LAYER M4 ;
        RECT  0.054 35.232 0.138 35.256 ;
    END
  END wupper[19]
  PIN wupper[1]
    DIRECTION INPUT ;
    USE SIGNAL ;
    PORT
      LAYER M4 ;
        RECT  0.054 31.584 0.138 31.608 ;
    END
  END wupper[1]
  PIN wupper[20]
    DIRECTION INPUT ;
    USE SIGNAL ;
    PORT
      LAYER M4 ;
        RECT  0.054 35.424 0.138 35.448 ;
    END
  END wupper[20]
  PIN wupper[21]
    DIRECTION INPUT ;
    USE SIGNAL ;
    PORT
      LAYER M4 ;
        RECT  0.054 35.616 0.138 35.64 ;
    END
  END wupper[21]
  PIN wupper[22]
    DIRECTION INPUT ;
    USE SIGNAL ;
    PORT
      LAYER M4 ;
        RECT  0.054 35.856 0.138 35.88 ;
    END
  END wupper[22]
  PIN wupper[23]
    DIRECTION INPUT ;
    USE SIGNAL ;
    PORT
      LAYER M4 ;
        RECT  0.054 36.048 0.138 36.072 ;
    END
  END wupper[23]
  PIN wupper[24]
    DIRECTION INPUT ;
    USE SIGNAL ;
    PORT
      LAYER M4 ;
        RECT  0.054 36.24 0.138 36.264 ;
    END
  END wupper[24]
  PIN wupper[25]
    DIRECTION INPUT ;
    USE SIGNAL ;
    PORT
      LAYER M4 ;
        RECT  0.054 36.432 0.138 36.456 ;
    END
  END wupper[25]
  PIN wupper[26]
    DIRECTION INPUT ;
    USE SIGNAL ;
    PORT
      LAYER M4 ;
        RECT  0.054 36.672 0.138 36.696 ;
    END
  END wupper[26]
  PIN wupper[27]
    DIRECTION INPUT ;
    USE SIGNAL ;
    PORT
      LAYER M4 ;
        RECT  0.054 36.864 0.138 36.888 ;
    END
  END wupper[27]
  PIN wupper[28]
    DIRECTION INPUT ;
    USE SIGNAL ;
    PORT
      LAYER M4 ;
        RECT  0.054 37.056 0.138 37.08 ;
    END
  END wupper[28]
  PIN wupper[29]
    DIRECTION INPUT ;
    USE SIGNAL ;
    PORT
      LAYER M4 ;
        RECT  0.054 37.248 0.138 37.272 ;
    END
  END wupper[29]
  PIN wupper[2]
    DIRECTION INPUT ;
    USE SIGNAL ;
    PORT
      LAYER M4 ;
        RECT  0.054 31.776 0.138 31.8 ;
    END
  END wupper[2]
  PIN wupper[30]
    DIRECTION INPUT ;
    USE SIGNAL ;
    PORT
      LAYER M4 ;
        RECT  0.054 37.44 0.138 37.464 ;
    END
  END wupper[30]
  PIN wupper[31]
    DIRECTION INPUT ;
    USE SIGNAL ;
    PORT
      LAYER M4 ;
        RECT  0.054 37.68 0.138 37.704 ;
    END
  END wupper[31]
  PIN wupper[32]
    DIRECTION INPUT ;
    USE SIGNAL ;
    PORT
      LAYER M4 ;
        RECT  0.054 37.872 0.138 37.896 ;
    END
  END wupper[32]
  PIN wupper[33]
    DIRECTION INPUT ;
    USE SIGNAL ;
    PORT
      LAYER M4 ;
        RECT  0.054 38.064 0.138 38.088 ;
    END
  END wupper[33]
  PIN wupper[34]
    DIRECTION INPUT ;
    USE SIGNAL ;
    PORT
      LAYER M4 ;
        RECT  0.054 38.256 0.138 38.28 ;
    END
  END wupper[34]
  PIN wupper[35]
    DIRECTION INPUT ;
    USE SIGNAL ;
    PORT
      LAYER M4 ;
        RECT  0.054 38.496 0.138 38.52 ;
    END
  END wupper[35]
  PIN wupper[36]
    DIRECTION INPUT ;
    USE SIGNAL ;
    PORT
      LAYER M4 ;
        RECT  0.054 38.688 0.138 38.712 ;
    END
  END wupper[36]
  PIN wupper[37]
    DIRECTION INPUT ;
    USE SIGNAL ;
    PORT
      LAYER M4 ;
        RECT  0.054 38.88 0.138 38.904 ;
    END
  END wupper[37]
  PIN wupper[38]
    DIRECTION INPUT ;
    USE SIGNAL ;
    PORT
      LAYER M4 ;
        RECT  0.054 39.072 0.138 39.096 ;
    END
  END wupper[38]
  PIN wupper[39]
    DIRECTION INPUT ;
    USE SIGNAL ;
    PORT
      LAYER M4 ;
        RECT  0.054 39.312 0.138 39.336 ;
    END
  END wupper[39]
  PIN wupper[3]
    DIRECTION INPUT ;
    USE SIGNAL ;
    PORT
      LAYER M4 ;
        RECT  0.054 31.968 0.138 31.992 ;
    END
  END wupper[3]
  PIN wupper[40]
    DIRECTION INPUT ;
    USE SIGNAL ;
    PORT
      LAYER M4 ;
        RECT  0.054 39.504 0.138 39.528 ;
    END
  END wupper[40]
  PIN wupper[41]
    DIRECTION INPUT ;
    USE SIGNAL ;
    PORT
      LAYER M4 ;
        RECT  0.054 39.696 0.138 39.72 ;
    END
  END wupper[41]
  PIN wupper[42]
    DIRECTION INPUT ;
    USE SIGNAL ;
    PORT
      LAYER M4 ;
        RECT  0.054 39.888 0.138 39.912 ;
    END
  END wupper[42]
  PIN wupper[43]
    DIRECTION INPUT ;
    USE SIGNAL ;
    PORT
      LAYER M4 ;
        RECT  0.054 40.08 0.138 40.104 ;
    END
  END wupper[43]
  PIN wupper[44]
    DIRECTION INPUT ;
    USE SIGNAL ;
    PORT
      LAYER M4 ;
        RECT  0.054 40.32 0.138 40.344 ;
    END
  END wupper[44]
  PIN wupper[45]
    DIRECTION INPUT ;
    USE SIGNAL ;
    PORT
      LAYER M4 ;
        RECT  0.054 40.512 0.138 40.536 ;
    END
  END wupper[45]
  PIN wupper[46]
    DIRECTION INPUT ;
    USE SIGNAL ;
    PORT
      LAYER M4 ;
        RECT  0.054 40.704 0.138 40.728 ;
    END
  END wupper[46]
  PIN wupper[47]
    DIRECTION INPUT ;
    USE SIGNAL ;
    PORT
      LAYER M4 ;
        RECT  0.054 40.896 0.138 40.92 ;
    END
  END wupper[47]
  PIN wupper[48]
    DIRECTION INPUT ;
    USE SIGNAL ;
    PORT
      LAYER M4 ;
        RECT  0.054 41.136 0.138 41.16 ;
    END
  END wupper[48]
  PIN wupper[49]
    DIRECTION INPUT ;
    USE SIGNAL ;
    PORT
      LAYER M4 ;
        RECT  0.054 41.328 0.138 41.352 ;
    END
  END wupper[49]
  PIN wupper[4]
    DIRECTION INPUT ;
    USE SIGNAL ;
    PORT
      LAYER M4 ;
        RECT  0.054 32.208 0.138 32.232 ;
    END
  END wupper[4]
  PIN wupper[50]
    DIRECTION INPUT ;
    USE SIGNAL ;
    PORT
      LAYER M4 ;
        RECT  0.054 41.52 0.138 41.544 ;
    END
  END wupper[50]
  PIN wupper[51]
    DIRECTION INPUT ;
    USE SIGNAL ;
    PORT
      LAYER M4 ;
        RECT  0.054 41.712 0.138 41.736 ;
    END
  END wupper[51]
  PIN wupper[52]
    DIRECTION INPUT ;
    USE SIGNAL ;
    PORT
      LAYER M4 ;
        RECT  0.054 41.952 0.138 41.976 ;
    END
  END wupper[52]
  PIN wupper[53]
    DIRECTION INPUT ;
    USE SIGNAL ;
    PORT
      LAYER M4 ;
        RECT  0.054 42.144 0.138 42.168 ;
    END
  END wupper[53]
  PIN wupper[54]
    DIRECTION INPUT ;
    USE SIGNAL ;
    PORT
      LAYER M4 ;
        RECT  0.054 42.336 0.138 42.36 ;
    END
  END wupper[54]
  PIN wupper[55]
    DIRECTION INPUT ;
    USE SIGNAL ;
    PORT
      LAYER M4 ;
        RECT  0.054 42.528 0.138 42.552 ;
    END
  END wupper[55]
  PIN wupper[56]
    DIRECTION INPUT ;
    USE SIGNAL ;
    PORT
      LAYER M4 ;
        RECT  0.054 42.72 0.138 42.744 ;
    END
  END wupper[56]
  PIN wupper[57]
    DIRECTION INPUT ;
    USE SIGNAL ;
    PORT
      LAYER M4 ;
        RECT  0.054 42.96 0.138 42.984 ;
    END
  END wupper[57]
  PIN wupper[58]
    DIRECTION INPUT ;
    USE SIGNAL ;
    PORT
      LAYER M4 ;
        RECT  0.054 43.152 0.138 43.176 ;
    END
  END wupper[58]
  PIN wupper[59]
    DIRECTION INPUT ;
    USE SIGNAL ;
    PORT
      LAYER M4 ;
        RECT  0.054 43.344 0.138 43.368 ;
    END
  END wupper[59]
  PIN wupper[5]
    DIRECTION INPUT ;
    USE SIGNAL ;
    PORT
      LAYER M4 ;
        RECT  0.054 32.4 0.138 32.424 ;
    END
  END wupper[5]
  PIN wupper[60]
    DIRECTION INPUT ;
    USE SIGNAL ;
    PORT
      LAYER M4 ;
        RECT  0.054 43.536 0.138 43.56 ;
    END
  END wupper[60]
  PIN wupper[61]
    DIRECTION INPUT ;
    USE SIGNAL ;
    PORT
      LAYER M4 ;
        RECT  0.054 43.776 0.138 43.8 ;
    END
  END wupper[61]
  PIN wupper[62]
    DIRECTION INPUT ;
    USE SIGNAL ;
    PORT
      LAYER M4 ;
        RECT  0.054 43.968 0.138 43.992 ;
    END
  END wupper[62]
  PIN wupper[63]
    DIRECTION INPUT ;
    USE SIGNAL ;
    PORT
      LAYER M4 ;
        RECT  0.054 44.16 0.138 44.184 ;
    END
  END wupper[63]
  PIN wupper[64]
    DIRECTION INPUT ;
    USE SIGNAL ;
    PORT
      LAYER M4 ;
        RECT  0.054 44.352 0.138 44.376 ;
    END
  END wupper[64]
  PIN wupper[65]
    DIRECTION INPUT ;
    USE SIGNAL ;
    PORT
      LAYER M4 ;
        RECT  0.054 44.592 0.138 44.616 ;
    END
  END wupper[65]
  PIN wupper[66]
    DIRECTION INPUT ;
    USE SIGNAL ;
    PORT
      LAYER M4 ;
        RECT  0.054 44.784 0.138 44.808 ;
    END
  END wupper[66]
  PIN wupper[67]
    DIRECTION INPUT ;
    USE SIGNAL ;
    PORT
      LAYER M4 ;
        RECT  0.054 44.976 0.138 45 ;
    END
  END wupper[67]
  PIN wupper[68]
    DIRECTION INPUT ;
    USE SIGNAL ;
    PORT
      LAYER M4 ;
        RECT  0.054 45.168 0.138 45.192 ;
    END
  END wupper[68]
  PIN wupper[69]
    DIRECTION INPUT ;
    USE SIGNAL ;
    PORT
      LAYER M4 ;
        RECT  0.054 45.36 0.138 45.384 ;
    END
  END wupper[69]
  PIN wupper[6]
    DIRECTION INPUT ;
    USE SIGNAL ;
    PORT
      LAYER M4 ;
        RECT  0.054 32.592 0.138 32.616 ;
    END
  END wupper[6]
  PIN wupper[70]
    DIRECTION INPUT ;
    USE SIGNAL ;
    PORT
      LAYER M4 ;
        RECT  0.054 45.6 0.138 45.624 ;
    END
  END wupper[70]
  PIN wupper[71]
    DIRECTION INPUT ;
    USE SIGNAL ;
    PORT
      LAYER M4 ;
        RECT  0.054 45.792 0.138 45.816 ;
    END
  END wupper[71]
  PIN wupper[72]
    DIRECTION INPUT ;
    USE SIGNAL ;
    PORT
      LAYER M4 ;
        RECT  0.054 45.984 0.138 46.008 ;
    END
  END wupper[72]
  PIN wupper[73]
    DIRECTION INPUT ;
    USE SIGNAL ;
    PORT
      LAYER M4 ;
        RECT  0.054 46.176 0.138 46.2 ;
    END
  END wupper[73]
  PIN wupper[74]
    DIRECTION INPUT ;
    USE SIGNAL ;
    PORT
      LAYER M4 ;
        RECT  0.054 46.416 0.138 46.44 ;
    END
  END wupper[74]
  PIN wupper[75]
    DIRECTION INPUT ;
    USE SIGNAL ;
    PORT
      LAYER M4 ;
        RECT  0.054 46.608 0.138 46.632 ;
    END
  END wupper[75]
  PIN wupper[76]
    DIRECTION INPUT ;
    USE SIGNAL ;
    PORT
      LAYER M4 ;
        RECT  0.054 46.8 0.138 46.824 ;
    END
  END wupper[76]
  PIN wupper[77]
    DIRECTION INPUT ;
    USE SIGNAL ;
    PORT
      LAYER M4 ;
        RECT  0.054 46.992 0.138 47.016 ;
    END
  END wupper[77]
  PIN wupper[78]
    DIRECTION INPUT ;
    USE SIGNAL ;
    PORT
      LAYER M4 ;
        RECT  0.054 47.184 0.138 47.208 ;
    END
  END wupper[78]
  PIN wupper[79]
    DIRECTION INPUT ;
    USE SIGNAL ;
    PORT
      LAYER M4 ;
        RECT  0.054 47.424 0.138 47.448 ;
    END
  END wupper[79]
  PIN wupper[7]
    DIRECTION INPUT ;
    USE SIGNAL ;
    PORT
      LAYER M4 ;
        RECT  0.054 32.784 0.138 32.808 ;
    END
  END wupper[7]
  PIN wupper[80]
    DIRECTION INPUT ;
    USE SIGNAL ;
    PORT
      LAYER M4 ;
        RECT  0.054 47.616 0.138 47.64 ;
    END
  END wupper[80]
  PIN wupper[81]
    DIRECTION INPUT ;
    USE SIGNAL ;
    PORT
      LAYER M4 ;
        RECT  0.054 47.808 0.138 47.832 ;
    END
  END wupper[81]
  PIN wupper[82]
    DIRECTION INPUT ;
    USE SIGNAL ;
    PORT
      LAYER M4 ;
        RECT  0.054 48 0.138 48.024 ;
    END
  END wupper[82]
  PIN wupper[83]
    DIRECTION INPUT ;
    USE SIGNAL ;
    PORT
      LAYER M4 ;
        RECT  0.054 48.24 0.138 48.264 ;
    END
  END wupper[83]
  PIN wupper[84]
    DIRECTION INPUT ;
    USE SIGNAL ;
    PORT
      LAYER M4 ;
        RECT  0.054 48.432 0.138 48.456 ;
    END
  END wupper[84]
  PIN wupper[85]
    DIRECTION INPUT ;
    USE SIGNAL ;
    PORT
      LAYER M4 ;
        RECT  0.054 48.624 0.138 48.648 ;
    END
  END wupper[85]
  PIN wupper[86]
    DIRECTION INPUT ;
    USE SIGNAL ;
    PORT
      LAYER M4 ;
        RECT  0.054 48.816 0.138 48.84 ;
    END
  END wupper[86]
  PIN wupper[87]
    DIRECTION INPUT ;
    USE SIGNAL ;
    PORT
      LAYER M4 ;
        RECT  0.054 49.056 0.138 49.08 ;
    END
  END wupper[87]
  PIN wupper[88]
    DIRECTION INPUT ;
    USE SIGNAL ;
    PORT
      LAYER M4 ;
        RECT  0.054 49.248 0.138 49.272 ;
    END
  END wupper[88]
  PIN wupper[89]
    DIRECTION INPUT ;
    USE SIGNAL ;
    PORT
      LAYER M4 ;
        RECT  0.054 49.44 0.138 49.464 ;
    END
  END wupper[89]
  PIN wupper[8]
    DIRECTION INPUT ;
    USE SIGNAL ;
    PORT
      LAYER M4 ;
        RECT  0.054 32.976 0.138 33 ;
    END
  END wupper[8]
  PIN wupper[90]
    DIRECTION INPUT ;
    USE SIGNAL ;
    PORT
      LAYER M4 ;
        RECT  0.054 49.632 0.138 49.656 ;
    END
  END wupper[90]
  PIN wupper[91]
    DIRECTION INPUT ;
    USE SIGNAL ;
    PORT
      LAYER M4 ;
        RECT  0.054 49.824 0.138 49.848 ;
    END
  END wupper[91]
  PIN wupper[92]
    DIRECTION INPUT ;
    USE SIGNAL ;
    PORT
      LAYER M4 ;
        RECT  0.054 50.064 0.138 50.088 ;
    END
  END wupper[92]
  PIN wupper[93]
    DIRECTION INPUT ;
    USE SIGNAL ;
    PORT
      LAYER M4 ;
        RECT  0.054 50.256 0.138 50.28 ;
    END
  END wupper[93]
  PIN wupper[94]
    DIRECTION INPUT ;
    USE SIGNAL ;
    PORT
      LAYER M4 ;
        RECT  0.054 50.448 0.138 50.472 ;
    END
  END wupper[94]
  PIN wupper[95]
    DIRECTION INPUT ;
    USE SIGNAL ;
    PORT
      LAYER M4 ;
        RECT  0.054 50.64 0.138 50.664 ;
    END
  END wupper[95]
  PIN wupper[96]
    DIRECTION INPUT ;
    USE SIGNAL ;
    PORT
      LAYER M4 ;
        RECT  0.054 50.88 0.138 50.904 ;
    END
  END wupper[96]
  PIN wupper[97]
    DIRECTION INPUT ;
    USE SIGNAL ;
    PORT
      LAYER M4 ;
        RECT  0.054 51.072 0.138 51.096 ;
    END
  END wupper[97]
  PIN wupper[98]
    DIRECTION INPUT ;
    USE SIGNAL ;
    PORT
      LAYER M4 ;
        RECT  0.054 51.264 0.138 51.288 ;
    END
  END wupper[98]
  PIN wupper[99]
    DIRECTION INPUT ;
    USE SIGNAL ;
    PORT
      LAYER M4 ;
        RECT  0.054 51.456 0.138 51.48 ;
    END
  END wupper[99]
  PIN wupper[9]
    DIRECTION INPUT ;
    USE SIGNAL ;
    PORT
      LAYER M4 ;
        RECT  0.054 33.216 0.138 33.24 ;
    END
  END wupper[9]
  PIN x[0]
    DIRECTION INPUT ;
    USE SIGNAL ;
    PORT
      LAYER M4 ;
        RECT  0.054 5.424 0.138 5.448 ;
    END
  END x[0]
  PIN x[100]
    DIRECTION INPUT ;
    USE SIGNAL ;
    PORT
      LAYER M4 ;
        RECT  0.054 25.68 0.138 25.704 ;
    END
  END x[100]
  PIN x[101]
    DIRECTION INPUT ;
    USE SIGNAL ;
    PORT
      LAYER M4 ;
        RECT  0.054 25.872 0.138 25.896 ;
    END
  END x[101]
  PIN x[102]
    DIRECTION INPUT ;
    USE SIGNAL ;
    PORT
      LAYER M4 ;
        RECT  0.054 26.112 0.138 26.136 ;
    END
  END x[102]
  PIN x[103]
    DIRECTION INPUT ;
    USE SIGNAL ;
    PORT
      LAYER M4 ;
        RECT  0.054 26.304 0.138 26.328 ;
    END
  END x[103]
  PIN x[104]
    DIRECTION INPUT ;
    USE SIGNAL ;
    PORT
      LAYER M4 ;
        RECT  0.054 26.496 0.138 26.52 ;
    END
  END x[104]
  PIN x[105]
    DIRECTION INPUT ;
    USE SIGNAL ;
    PORT
      LAYER M4 ;
        RECT  0.054 26.688 0.138 26.712 ;
    END
  END x[105]
  PIN x[106]
    DIRECTION INPUT ;
    USE SIGNAL ;
    PORT
      LAYER M4 ;
        RECT  0.054 26.928 0.138 26.952 ;
    END
  END x[106]
  PIN x[107]
    DIRECTION INPUT ;
    USE SIGNAL ;
    PORT
      LAYER M4 ;
        RECT  0.054 27.12 0.138 27.144 ;
    END
  END x[107]
  PIN x[108]
    DIRECTION INPUT ;
    USE SIGNAL ;
    PORT
      LAYER M4 ;
        RECT  0.054 27.312 0.138 27.336 ;
    END
  END x[108]
  PIN x[109]
    DIRECTION INPUT ;
    USE SIGNAL ;
    PORT
      LAYER M4 ;
        RECT  0.054 27.504 0.138 27.528 ;
    END
  END x[109]
  PIN x[10]
    DIRECTION INPUT ;
    USE SIGNAL ;
    PORT
      LAYER M4 ;
        RECT  0.054 7.44 0.138 7.464 ;
    END
  END x[10]
  PIN x[110]
    DIRECTION INPUT ;
    USE SIGNAL ;
    PORT
      LAYER M4 ;
        RECT  0.054 27.696 0.138 27.72 ;
    END
  END x[110]
  PIN x[111]
    DIRECTION INPUT ;
    USE SIGNAL ;
    PORT
      LAYER M4 ;
        RECT  0.054 27.936 0.138 27.96 ;
    END
  END x[111]
  PIN x[112]
    DIRECTION INPUT ;
    USE SIGNAL ;
    PORT
      LAYER M4 ;
        RECT  0.054 28.128 0.138 28.152 ;
    END
  END x[112]
  PIN x[113]
    DIRECTION INPUT ;
    USE SIGNAL ;
    PORT
      LAYER M4 ;
        RECT  0.054 28.32 0.138 28.344 ;
    END
  END x[113]
  PIN x[114]
    DIRECTION INPUT ;
    USE SIGNAL ;
    PORT
      LAYER M4 ;
        RECT  0.054 28.512 0.138 28.536 ;
    END
  END x[114]
  PIN x[115]
    DIRECTION INPUT ;
    USE SIGNAL ;
    PORT
      LAYER M4 ;
        RECT  0.054 28.752 0.138 28.776 ;
    END
  END x[115]
  PIN x[116]
    DIRECTION INPUT ;
    USE SIGNAL ;
    PORT
      LAYER M4 ;
        RECT  0.054 28.944 0.138 28.968 ;
    END
  END x[116]
  PIN x[117]
    DIRECTION INPUT ;
    USE SIGNAL ;
    PORT
      LAYER M4 ;
        RECT  0.054 29.136 0.138 29.16 ;
    END
  END x[117]
  PIN x[118]
    DIRECTION INPUT ;
    USE SIGNAL ;
    PORT
      LAYER M4 ;
        RECT  0.054 29.328 0.138 29.352 ;
    END
  END x[118]
  PIN x[119]
    DIRECTION INPUT ;
    USE SIGNAL ;
    PORT
      LAYER M4 ;
        RECT  0.054 29.568 0.138 29.592 ;
    END
  END x[119]
  PIN x[11]
    DIRECTION INPUT ;
    USE SIGNAL ;
    PORT
      LAYER M4 ;
        RECT  0.054 7.632 0.138 7.656 ;
    END
  END x[11]
  PIN x[120]
    DIRECTION INPUT ;
    USE SIGNAL ;
    PORT
      LAYER M4 ;
        RECT  0.054 29.76 0.138 29.784 ;
    END
  END x[120]
  PIN x[121]
    DIRECTION INPUT ;
    USE SIGNAL ;
    PORT
      LAYER M4 ;
        RECT  0.054 29.952 0.138 29.976 ;
    END
  END x[121]
  PIN x[122]
    DIRECTION INPUT ;
    USE SIGNAL ;
    PORT
      LAYER M4 ;
        RECT  0.054 30.144 0.138 30.168 ;
    END
  END x[122]
  PIN x[123]
    DIRECTION INPUT ;
    USE SIGNAL ;
    PORT
      LAYER M4 ;
        RECT  0.054 30.336 0.138 30.36 ;
    END
  END x[123]
  PIN x[124]
    DIRECTION INPUT ;
    USE SIGNAL ;
    PORT
      LAYER M4 ;
        RECT  0.054 30.576 0.138 30.6 ;
    END
  END x[124]
  PIN x[125]
    DIRECTION INPUT ;
    USE SIGNAL ;
    PORT
      LAYER M4 ;
        RECT  0.054 30.768 0.138 30.792 ;
    END
  END x[125]
  PIN x[126]
    DIRECTION INPUT ;
    USE SIGNAL ;
    PORT
      LAYER M4 ;
        RECT  0.054 30.96 0.138 30.984 ;
    END
    PORT
      LAYER M4 ;
        RECT  0.025 30.96 0.085 31.08 ;
    END
    PORT
      LAYER M4 ;
        RECT  0.085 30.864 0.108 31.08 ;
    END
  END x[126]
  PIN x[127]
    DIRECTION INPUT ;
    USE SIGNAL ;
    PORT
      LAYER M4 ;
        RECT  0.054 31.152 0.138 31.176 ;
    END
  END x[127]
  PIN x[12]
    DIRECTION INPUT ;
    USE SIGNAL ;
    PORT
      LAYER M4 ;
        RECT  0.054 7.824 0.138 7.848 ;
    END
  END x[12]
  PIN x[13]
    DIRECTION INPUT ;
    USE SIGNAL ;
    PORT
      LAYER M4 ;
        RECT  0.054 8.016 0.138 8.04 ;
    END
  END x[13]
  PIN x[14]
    DIRECTION INPUT ;
    USE SIGNAL ;
    PORT
      LAYER M4 ;
        RECT  0.054 8.208 0.138 8.232 ;
    END
  END x[14]
  PIN x[15]
    DIRECTION INPUT ;
    USE SIGNAL ;
    PORT
      LAYER M4 ;
        RECT  0.054 8.448 0.138 8.472 ;
    END
  END x[15]
  PIN x[16]
    DIRECTION INPUT ;
    USE SIGNAL ;
    PORT
      LAYER M4 ;
        RECT  0.054 8.64 0.138 8.664 ;
    END
  END x[16]
  PIN x[17]
    DIRECTION INPUT ;
    USE SIGNAL ;
    PORT
      LAYER M4 ;
        RECT  0.054 8.832 0.138 8.856 ;
    END
  END x[17]
  PIN x[18]
    DIRECTION INPUT ;
    USE SIGNAL ;
    PORT
      LAYER M4 ;
        RECT  0.054 9.024 0.138 9.048 ;
    END
  END x[18]
  PIN x[19]
    DIRECTION INPUT ;
    USE SIGNAL ;
    PORT
      LAYER M4 ;
        RECT  0.054 9.264 0.138 9.288 ;
    END
  END x[19]
  PIN x[1]
    DIRECTION INPUT ;
    USE SIGNAL ;
    PORT
      LAYER M4 ;
        RECT  0.054 5.568 0.138 5.592 ;
    END
  END x[1]
  PIN x[20]
    DIRECTION INPUT ;
    USE SIGNAL ;
    PORT
      LAYER M4 ;
        RECT  0.054 9.456 0.138 9.48 ;
    END
  END x[20]
  PIN x[21]
    DIRECTION INPUT ;
    USE SIGNAL ;
    PORT
      LAYER M4 ;
        RECT  0.054 9.648 0.138 9.672 ;
    END
  END x[21]
  PIN x[22]
    DIRECTION INPUT ;
    USE SIGNAL ;
    PORT
      LAYER M4 ;
        RECT  0.054 9.84 0.138 9.864 ;
    END
  END x[22]
  PIN x[23]
    DIRECTION INPUT ;
    USE SIGNAL ;
    PORT
      LAYER M4 ;
        RECT  0.054 10.08 0.138 10.104 ;
    END
  END x[23]
  PIN x[24]
    DIRECTION INPUT ;
    USE SIGNAL ;
    PORT
      LAYER M4 ;
        RECT  0.054 10.272 0.138 10.296 ;
    END
  END x[24]
  PIN x[25]
    DIRECTION INPUT ;
    USE SIGNAL ;
    PORT
      LAYER M4 ;
        RECT  0.054 10.464 0.138 10.488 ;
    END
  END x[25]
  PIN x[26]
    DIRECTION INPUT ;
    USE SIGNAL ;
    PORT
      LAYER M4 ;
        RECT  0.054 10.656 0.138 10.68 ;
    END
  END x[26]
  PIN x[27]
    DIRECTION INPUT ;
    USE SIGNAL ;
    PORT
      LAYER M4 ;
        RECT  0.054 10.848 0.138 10.872 ;
    END
  END x[27]
  PIN x[28]
    DIRECTION INPUT ;
    USE SIGNAL ;
    PORT
      LAYER M4 ;
        RECT  0.054 11.088 0.138 11.112 ;
    END
  END x[28]
  PIN x[29]
    DIRECTION INPUT ;
    USE SIGNAL ;
    PORT
      LAYER M4 ;
        RECT  0.054 11.28 0.138 11.304 ;
    END
  END x[29]
  PIN x[2]
    DIRECTION INPUT ;
    USE SIGNAL ;
    PORT
      LAYER M4 ;
        RECT  0.054 5.808 0.138 5.832 ;
    END
  END x[2]
  PIN x[30]
    DIRECTION INPUT ;
    USE SIGNAL ;
    PORT
      LAYER M4 ;
        RECT  0.054 11.472 0.138 11.496 ;
    END
  END x[30]
  PIN x[31]
    DIRECTION INPUT ;
    USE SIGNAL ;
    PORT
      LAYER M4 ;
        RECT  0.054 11.664 0.138 11.688 ;
    END
  END x[31]
  PIN x[32]
    DIRECTION INPUT ;
    USE SIGNAL ;
    PORT
      LAYER M4 ;
        RECT  0.054 11.904 0.138 11.928 ;
    END
  END x[32]
  PIN x[33]
    DIRECTION INPUT ;
    USE SIGNAL ;
    PORT
      LAYER M4 ;
        RECT  0.054 12.096 0.138 12.12 ;
    END
  END x[33]
  PIN x[34]
    DIRECTION INPUT ;
    USE SIGNAL ;
    PORT
      LAYER M4 ;
        RECT  0.054 12.288 0.138 12.312 ;
    END
  END x[34]
  PIN x[35]
    DIRECTION INPUT ;
    USE SIGNAL ;
    PORT
      LAYER M4 ;
        RECT  0.054 12.48 0.138 12.504 ;
    END
  END x[35]
  PIN x[36]
    DIRECTION INPUT ;
    USE SIGNAL ;
    PORT
      LAYER M4 ;
        RECT  0.054 12.72 0.138 12.744 ;
    END
  END x[36]
  PIN x[37]
    DIRECTION INPUT ;
    USE SIGNAL ;
    PORT
      LAYER M4 ;
        RECT  0.054 12.912 0.138 12.936 ;
    END
  END x[37]
  PIN x[38]
    DIRECTION INPUT ;
    USE SIGNAL ;
    PORT
      LAYER M4 ;
        RECT  0.054 13.104 0.138 13.128 ;
    END
  END x[38]
  PIN x[39]
    DIRECTION INPUT ;
    USE SIGNAL ;
    PORT
      LAYER M4 ;
        RECT  0.054 13.296 0.138 13.32 ;
    END
  END x[39]
  PIN x[3]
    DIRECTION INPUT ;
    USE SIGNAL ;
    PORT
      LAYER M4 ;
        RECT  0.054 6 0.138 6.024 ;
    END
  END x[3]
  PIN x[40]
    DIRECTION INPUT ;
    USE SIGNAL ;
    PORT
      LAYER M4 ;
        RECT  0.054 13.488 0.138 13.512 ;
    END
  END x[40]
  PIN x[41]
    DIRECTION INPUT ;
    USE SIGNAL ;
    PORT
      LAYER M4 ;
        RECT  0.054 13.728 0.138 13.752 ;
    END
  END x[41]
  PIN x[42]
    DIRECTION INPUT ;
    USE SIGNAL ;
    PORT
      LAYER M4 ;
        RECT  0.054 13.92 0.138 13.944 ;
    END
  END x[42]
  PIN x[43]
    DIRECTION INPUT ;
    USE SIGNAL ;
    PORT
      LAYER M4 ;
        RECT  0.054 14.112 0.138 14.136 ;
    END
  END x[43]
  PIN x[44]
    DIRECTION INPUT ;
    USE SIGNAL ;
    PORT
      LAYER M4 ;
        RECT  0.054 14.304 0.138 14.328 ;
    END
  END x[44]
  PIN x[45]
    DIRECTION INPUT ;
    USE SIGNAL ;
    PORT
      LAYER M4 ;
        RECT  0.054 14.544 0.138 14.568 ;
    END
  END x[45]
  PIN x[46]
    DIRECTION INPUT ;
    USE SIGNAL ;
    PORT
      LAYER M4 ;
        RECT  0.054 14.736 0.138 14.76 ;
    END
  END x[46]
  PIN x[47]
    DIRECTION INPUT ;
    USE SIGNAL ;
    PORT
      LAYER M4 ;
        RECT  0.054 14.928 0.138 14.952 ;
    END
  END x[47]
  PIN x[48]
    DIRECTION INPUT ;
    USE SIGNAL ;
    PORT
      LAYER M4 ;
        RECT  0.054 15.12 0.138 15.144 ;
    END
  END x[48]
  PIN x[49]
    DIRECTION INPUT ;
    USE SIGNAL ;
    PORT
      LAYER M4 ;
        RECT  0.054 15.312 0.138 15.336 ;
    END
  END x[49]
  PIN x[4]
    DIRECTION INPUT ;
    USE SIGNAL ;
    PORT
      LAYER M4 ;
        RECT  0.054 6.192 0.138 6.216 ;
    END
  END x[4]
  PIN x[50]
    DIRECTION INPUT ;
    USE SIGNAL ;
    PORT
      LAYER M4 ;
        RECT  0.054 15.552 0.138 15.576 ;
    END
  END x[50]
  PIN x[51]
    DIRECTION INPUT ;
    USE SIGNAL ;
    PORT
      LAYER M4 ;
        RECT  0.054 15.744 0.138 15.768 ;
    END
  END x[51]
  PIN x[52]
    DIRECTION INPUT ;
    USE SIGNAL ;
    PORT
      LAYER M4 ;
        RECT  0.054 15.936 0.138 15.96 ;
    END
  END x[52]
  PIN x[53]
    DIRECTION INPUT ;
    USE SIGNAL ;
    PORT
      LAYER M4 ;
        RECT  0.054 16.128 0.138 16.152 ;
    END
  END x[53]
  PIN x[54]
    DIRECTION INPUT ;
    USE SIGNAL ;
    PORT
      LAYER M4 ;
        RECT  0.054 16.368 0.138 16.392 ;
    END
  END x[54]
  PIN x[55]
    DIRECTION INPUT ;
    USE SIGNAL ;
    PORT
      LAYER M4 ;
        RECT  0.054 16.56 0.138 16.584 ;
    END
  END x[55]
  PIN x[56]
    DIRECTION INPUT ;
    USE SIGNAL ;
    PORT
      LAYER M4 ;
        RECT  0.054 16.752 0.138 16.776 ;
    END
  END x[56]
  PIN x[57]
    DIRECTION INPUT ;
    USE SIGNAL ;
    PORT
      LAYER M4 ;
        RECT  0.054 16.944 0.138 16.968 ;
    END
  END x[57]
  PIN x[58]
    DIRECTION INPUT ;
    USE SIGNAL ;
    PORT
      LAYER M4 ;
        RECT  0.054 17.184 0.138 17.208 ;
    END
  END x[58]
  PIN x[59]
    DIRECTION INPUT ;
    USE SIGNAL ;
    PORT
      LAYER M4 ;
        RECT  0.054 17.376 0.138 17.4 ;
    END
  END x[59]
  PIN x[5]
    DIRECTION INPUT ;
    USE SIGNAL ;
    PORT
      LAYER M4 ;
        RECT  0.054 6.384 0.138 6.408 ;
    END
  END x[5]
  PIN x[60]
    DIRECTION INPUT ;
    USE SIGNAL ;
    PORT
      LAYER M4 ;
        RECT  0.054 17.568 0.138 17.592 ;
    END
  END x[60]
  PIN x[61]
    DIRECTION INPUT ;
    USE SIGNAL ;
    PORT
      LAYER M4 ;
        RECT  0.054 17.76 0.138 17.784 ;
    END
  END x[61]
  PIN x[62]
    DIRECTION INPUT ;
    USE SIGNAL ;
    PORT
      LAYER M4 ;
        RECT  0.054 17.952 0.138 17.976 ;
    END
  END x[62]
  PIN x[63]
    DIRECTION INPUT ;
    USE SIGNAL ;
    PORT
      LAYER M4 ;
        RECT  0.054 18.192 0.138 18.216 ;
    END
  END x[63]
  PIN x[64]
    DIRECTION INPUT ;
    USE SIGNAL ;
    PORT
      LAYER M4 ;
        RECT  0.054 18.384 0.138 18.408 ;
    END
  END x[64]
  PIN x[65]
    DIRECTION INPUT ;
    USE SIGNAL ;
    PORT
      LAYER M4 ;
        RECT  0.054 18.576 0.138 18.6 ;
    END
  END x[65]
  PIN x[66]
    DIRECTION INPUT ;
    USE SIGNAL ;
    PORT
      LAYER M4 ;
        RECT  0.054 18.768 0.138 18.792 ;
    END
  END x[66]
  PIN x[67]
    DIRECTION INPUT ;
    USE SIGNAL ;
    PORT
      LAYER M4 ;
        RECT  0.054 19.008 0.138 19.032 ;
    END
  END x[67]
  PIN x[68]
    DIRECTION INPUT ;
    USE SIGNAL ;
    PORT
      LAYER M4 ;
        RECT  0.054 19.2 0.138 19.224 ;
    END
  END x[68]
  PIN x[69]
    DIRECTION INPUT ;
    USE SIGNAL ;
    PORT
      LAYER M4 ;
        RECT  0.054 19.392 0.138 19.416 ;
    END
  END x[69]
  PIN x[6]
    DIRECTION INPUT ;
    USE SIGNAL ;
    PORT
      LAYER M4 ;
        RECT  0.054 6.624 0.138 6.648 ;
    END
  END x[6]
  PIN x[70]
    DIRECTION INPUT ;
    USE SIGNAL ;
    PORT
      LAYER M4 ;
        RECT  0.054 19.584 0.138 19.608 ;
    END
  END x[70]
  PIN x[71]
    DIRECTION INPUT ;
    USE SIGNAL ;
    PORT
      LAYER M4 ;
        RECT  0.054 19.824 0.138 19.848 ;
    END
  END x[71]
  PIN x[72]
    DIRECTION INPUT ;
    USE SIGNAL ;
    PORT
      LAYER M4 ;
        RECT  0.054 20.016 0.138 20.04 ;
    END
  END x[72]
  PIN x[73]
    DIRECTION INPUT ;
    USE SIGNAL ;
    PORT
      LAYER M4 ;
        RECT  0.054 20.208 0.138 20.232 ;
    END
  END x[73]
  PIN x[74]
    DIRECTION INPUT ;
    USE SIGNAL ;
    PORT
      LAYER M4 ;
        RECT  0.054 20.4 0.138 20.424 ;
    END
  END x[74]
  PIN x[75]
    DIRECTION INPUT ;
    USE SIGNAL ;
    PORT
      LAYER M4 ;
        RECT  0.054 20.592 0.138 20.616 ;
    END
  END x[75]
  PIN x[76]
    DIRECTION INPUT ;
    USE SIGNAL ;
    PORT
      LAYER M4 ;
        RECT  0.054 20.832 0.138 20.856 ;
    END
  END x[76]
  PIN x[77]
    DIRECTION INPUT ;
    USE SIGNAL ;
    PORT
      LAYER M4 ;
        RECT  0.054 21.024 0.138 21.048 ;
    END
  END x[77]
  PIN x[78]
    DIRECTION INPUT ;
    USE SIGNAL ;
    PORT
      LAYER M4 ;
        RECT  0.054 21.216 0.138 21.24 ;
    END
  END x[78]
  PIN x[79]
    DIRECTION INPUT ;
    USE SIGNAL ;
    PORT
      LAYER M4 ;
        RECT  0.054 21.408 0.138 21.432 ;
    END
  END x[79]
  PIN x[7]
    DIRECTION INPUT ;
    USE SIGNAL ;
    PORT
      LAYER M4 ;
        RECT  0.054 6.816 0.138 6.84 ;
    END
  END x[7]
  PIN x[80]
    DIRECTION INPUT ;
    USE SIGNAL ;
    PORT
      LAYER M4 ;
        RECT  0.054 21.648 0.138 21.672 ;
    END
  END x[80]
  PIN x[81]
    DIRECTION INPUT ;
    USE SIGNAL ;
    PORT
      LAYER M4 ;
        RECT  0.054 21.84 0.138 21.864 ;
    END
  END x[81]
  PIN x[82]
    DIRECTION INPUT ;
    USE SIGNAL ;
    PORT
      LAYER M4 ;
        RECT  0.054 22.032 0.138 22.056 ;
    END
  END x[82]
  PIN x[83]
    DIRECTION INPUT ;
    USE SIGNAL ;
    PORT
      LAYER M4 ;
        RECT  0.054 22.224 0.138 22.248 ;
    END
  END x[83]
  PIN x[84]
    DIRECTION INPUT ;
    USE SIGNAL ;
    PORT
      LAYER M4 ;
        RECT  0.054 22.464 0.138 22.488 ;
    END
  END x[84]
  PIN x[85]
    DIRECTION INPUT ;
    USE SIGNAL ;
    PORT
      LAYER M4 ;
        RECT  0.054 22.656 0.138 22.68 ;
    END
  END x[85]
  PIN x[86]
    DIRECTION INPUT ;
    USE SIGNAL ;
    PORT
      LAYER M4 ;
        RECT  0.054 22.848 0.138 22.872 ;
    END
  END x[86]
  PIN x[87]
    DIRECTION INPUT ;
    USE SIGNAL ;
    PORT
      LAYER M4 ;
        RECT  0.054 23.04 0.138 23.064 ;
    END
  END x[87]
  PIN x[88]
    DIRECTION INPUT ;
    USE SIGNAL ;
    PORT
      LAYER M4 ;
        RECT  0.054 23.232 0.138 23.256 ;
    END
  END x[88]
  PIN x[89]
    DIRECTION INPUT ;
    USE SIGNAL ;
    PORT
      LAYER M4 ;
        RECT  0.054 23.472 0.138 23.496 ;
    END
  END x[89]
  PIN x[8]
    DIRECTION INPUT ;
    USE SIGNAL ;
    PORT
      LAYER M4 ;
        RECT  0.054 7.008 0.138 7.032 ;
    END
  END x[8]
  PIN x[90]
    DIRECTION INPUT ;
    USE SIGNAL ;
    PORT
      LAYER M4 ;
        RECT  0.054 23.664 0.138 23.688 ;
    END
  END x[90]
  PIN x[91]
    DIRECTION INPUT ;
    USE SIGNAL ;
    PORT
      LAYER M4 ;
        RECT  0.054 23.856 0.138 23.88 ;
    END
  END x[91]
  PIN x[92]
    DIRECTION INPUT ;
    USE SIGNAL ;
    PORT
      LAYER M4 ;
        RECT  0.054 24.048 0.138 24.072 ;
    END
  END x[92]
  PIN x[93]
    DIRECTION INPUT ;
    USE SIGNAL ;
    PORT
      LAYER M4 ;
        RECT  0.054 24.288 0.138 24.312 ;
    END
  END x[93]
  PIN x[94]
    DIRECTION INPUT ;
    USE SIGNAL ;
    PORT
      LAYER M4 ;
        RECT  0.054 24.48 0.138 24.504 ;
    END
  END x[94]
  PIN x[95]
    DIRECTION INPUT ;
    USE SIGNAL ;
    PORT
      LAYER M4 ;
        RECT  0.054 24.672 0.138 24.696 ;
    END
  END x[95]
  PIN x[96]
    DIRECTION INPUT ;
    USE SIGNAL ;
    PORT
      LAYER M4 ;
        RECT  0.054 24.864 0.138 24.888 ;
    END
  END x[96]
  PIN x[97]
    DIRECTION INPUT ;
    USE SIGNAL ;
    PORT
      LAYER M4 ;
        RECT  0.054 25.056 0.138 25.08 ;
    END
  END x[97]
  PIN x[98]
    DIRECTION INPUT ;
    USE SIGNAL ;
    PORT
      LAYER M4 ;
        RECT  0.054 25.296 0.138 25.32 ;
    END
  END x[98]
  PIN x[99]
    DIRECTION INPUT ;
    USE SIGNAL ;
    PORT
      LAYER M4 ;
        RECT  0.054 25.488 0.138 25.512 ;
    END
  END x[99]
  PIN x[9]
    DIRECTION INPUT ;
    USE SIGNAL ;
    PORT
      LAYER M4 ;
        RECT  0.054 7.2 0.138 7.224 ;
    END
  END x[9]
  PIN VDD
    DIRECTION INOUT ;
    USE POWER ;
    PORT
      LAYER M5 ;
        RECT  10.692 2.151 10.812 62.649 ;
        RECT  7.992 2.151 8.112 62.649 ;
        RECT  5.292 2.151 5.412 62.649 ;
        RECT  2.592 2.151 2.712 62.649 ;
    END
  END VDD
  PIN VSS
    DIRECTION INOUT ;
    USE GROUND ;
    PORT
      LAYER M5 ;
        RECT  10.5 2.137 10.62 62.663 ;
        RECT  7.8 2.137 7.92 62.663 ;
        RECT  5.1 2.137 5.22 62.663 ;
        RECT  2.4 2.137 2.52 62.663 ;
    END
  END VSS
  # OT_OBS_CLOSED layer=M5 d_um=1.536 added=61
  OBS
    LAYER RVTN ;
     RECT  2.16 2.16 12.96 2.295 ;
     RECT  2.16 2.565 12.96 2.835 ;
     RECT  2.16 3.105 12.96 3.375 ;
     RECT  2.16 3.645 12.96 3.915 ;
     RECT  2.16 4.185 12.96 4.455 ;
     RECT  2.16 4.725 12.96 4.995 ;
     RECT  2.16 5.265 12.96 5.535 ;
     RECT  2.16 5.805 12.96 6.075 ;
     RECT  2.16 6.345 12.96 6.615 ;
     RECT  2.16 6.885 12.96 7.155 ;
     RECT  2.16 7.425 12.96 7.695 ;
     RECT  2.16 7.965 12.96 8.235 ;
     RECT  2.16 8.505 12.96 8.775 ;
     RECT  2.16 9.045 12.96 9.315 ;
     RECT  2.16 9.585 12.96 9.855 ;
     RECT  2.16 10.125 12.96 10.395 ;
     RECT  2.16 10.665 12.96 10.935 ;
     RECT  2.16 11.205 12.96 11.475 ;
     RECT  2.16 11.745 12.96 12.015 ;
     RECT  2.16 12.285 12.96 12.555 ;
     RECT  2.16 12.825 12.96 13.095 ;
     RECT  2.16 13.365 12.96 13.635 ;
     RECT  2.16 13.905 12.96 14.175 ;
     RECT  2.16 14.445 12.96 14.715 ;
     RECT  2.16 14.985 12.96 15.255 ;
     RECT  2.16 15.525 12.96 15.795 ;
     RECT  2.16 16.065 12.96 16.335 ;
     RECT  2.16 16.605 12.96 16.875 ;
     RECT  2.16 17.145 12.96 17.415 ;
     RECT  2.16 17.685 12.96 17.955 ;
     RECT  2.16 18.225 12.96 18.495 ;
     RECT  2.16 18.765 12.96 19.035 ;
     RECT  2.16 19.305 12.96 19.575 ;
     RECT  2.16 19.845 12.96 20.115 ;
     RECT  2.16 20.385 12.96 20.655 ;
     RECT  2.16 20.925 12.96 21.195 ;
     RECT  2.16 21.465 12.96 21.735 ;
     RECT  2.16 22.005 12.96 22.275 ;
     RECT  2.16 22.545 12.96 22.815 ;
     RECT  2.16 23.085 12.96 23.355 ;
     RECT  2.16 23.625 12.96 23.895 ;
     RECT  2.16 24.165 12.96 24.435 ;
     RECT  2.16 24.705 12.96 24.975 ;
     RECT  2.16 25.245 12.96 25.515 ;
     RECT  2.16 25.785 12.96 26.055 ;
     RECT  2.16 26.325 12.96 26.595 ;
     RECT  2.16 26.865 12.96 27.135 ;
     RECT  2.16 27.405 12.96 27.675 ;
     RECT  2.16 27.945 12.96 28.215 ;
     RECT  2.16 28.485 12.96 28.755 ;
     RECT  2.16 29.025 12.96 29.295 ;
     RECT  2.16 29.565 12.96 29.835 ;
     RECT  2.16 30.105 12.96 30.375 ;
     RECT  2.16 30.645 12.96 30.915 ;
     RECT  2.16 31.185 12.96 31.455 ;
     RECT  2.16 31.725 12.96 31.995 ;
     RECT  2.16 32.265 12.96 32.535 ;
     RECT  2.16 32.805 12.96 33.075 ;
     RECT  2.16 33.345 12.96 33.615 ;
     RECT  2.16 33.885 12.96 34.155 ;
     RECT  2.16 34.425 12.96 34.695 ;
     RECT  2.16 34.965 12.96 35.235 ;
     RECT  2.16 35.505 12.96 35.775 ;
     RECT  2.16 36.045 12.96 36.315 ;
     RECT  2.16 36.585 12.96 36.855 ;
     RECT  2.16 37.125 12.96 37.395 ;
     RECT  2.16 37.665 12.96 37.935 ;
     RECT  2.16 38.205 12.96 38.475 ;
     RECT  2.16 38.745 12.96 39.015 ;
     RECT  2.16 39.285 12.96 39.555 ;
     RECT  2.16 39.825 12.96 40.095 ;
     RECT  2.16 40.365 12.96 40.635 ;
     RECT  2.16 40.905 12.96 41.175 ;
     RECT  2.16 41.445 12.96 41.715 ;
     RECT  2.16 41.985 12.96 42.255 ;
     RECT  2.16 42.525 12.96 42.795 ;
     RECT  2.16 43.065 12.96 43.335 ;
     RECT  2.16 43.605 12.96 43.875 ;
     RECT  2.16 44.145 12.96 44.415 ;
     RECT  2.16 44.685 12.96 44.955 ;
     RECT  2.16 45.225 12.96 45.495 ;
     RECT  2.16 45.765 12.96 46.035 ;
     RECT  2.16 46.305 12.96 46.575 ;
     RECT  2.16 46.845 12.96 47.115 ;
     RECT  2.16 47.385 12.96 47.655 ;
     RECT  2.16 47.925 12.96 48.195 ;
     RECT  2.16 48.465 12.96 48.735 ;
     RECT  2.16 49.005 12.96 49.275 ;
     RECT  2.16 49.545 12.96 49.815 ;
     RECT  2.16 50.085 12.96 50.355 ;
     RECT  2.16 50.625 12.96 50.895 ;
     RECT  2.16 51.165 12.96 51.435 ;
     RECT  2.16 51.705 12.96 51.975 ;
     RECT  2.16 52.245 12.96 52.515 ;
     RECT  2.16 52.785 12.96 53.055 ;
     RECT  2.16 53.325 12.96 53.595 ;
     RECT  2.16 53.865 12.96 54.135 ;
     RECT  2.16 54.405 12.96 54.675 ;
     RECT  2.16 54.945 12.96 55.215 ;
     RECT  2.16 55.485 12.96 55.755 ;
     RECT  2.16 56.025 12.96 56.295 ;
     RECT  2.16 56.565 12.96 56.835 ;
     RECT  2.16 57.105 12.96 57.375 ;
     RECT  2.16 57.645 12.96 57.915 ;
     RECT  2.16 58.185 12.96 58.455 ;
     RECT  2.16 58.725 12.96 58.995 ;
     RECT  2.16 59.265 12.96 59.535 ;
     RECT  2.16 59.805 12.96 60.075 ;
     RECT  2.16 60.345 12.96 60.615 ;
     RECT  2.16 60.885 12.96 61.155 ;
     RECT  2.16 61.425 12.96 61.695 ;
     RECT  2.16 61.965 12.96 62.235 ;
     RECT  2.16 62.505 12.96 62.64 ;
    LAYER RVTP ;
     RECT  2.16 2.295 12.96 2.565 ;
     RECT  2.16 2.835 12.96 3.105 ;
     RECT  2.16 3.375 12.96 3.645 ;
     RECT  2.16 3.915 12.96 4.185 ;
     RECT  2.16 4.455 12.96 4.725 ;
     RECT  2.16 4.995 12.96 5.265 ;
     RECT  2.16 5.535 12.96 5.805 ;
     RECT  2.16 6.075 12.96 6.345 ;
     RECT  2.16 6.615 12.96 6.885 ;
     RECT  2.16 7.155 12.96 7.425 ;
     RECT  2.16 7.695 12.96 7.965 ;
     RECT  2.16 8.235 12.96 8.505 ;
     RECT  2.16 8.775 12.96 9.045 ;
     RECT  2.16 9.315 12.96 9.585 ;
     RECT  2.16 9.855 12.96 10.125 ;
     RECT  2.16 10.395 12.96 10.665 ;
     RECT  2.16 10.935 12.96 11.205 ;
     RECT  2.16 11.475 12.96 11.745 ;
     RECT  2.16 12.015 12.96 12.285 ;
     RECT  2.16 12.555 12.96 12.825 ;
     RECT  2.16 13.095 12.96 13.365 ;
     RECT  2.16 13.635 12.96 13.905 ;
     RECT  2.16 14.175 12.96 14.445 ;
     RECT  2.16 14.715 12.96 14.985 ;
     RECT  2.16 15.255 12.96 15.525 ;
     RECT  2.16 15.795 12.96 16.065 ;
     RECT  2.16 16.335 12.96 16.605 ;
     RECT  2.16 16.875 12.96 17.145 ;
     RECT  2.16 17.415 12.96 17.685 ;
     RECT  2.16 17.955 12.96 18.225 ;
     RECT  2.16 18.495 12.96 18.765 ;
     RECT  2.16 19.035 12.96 19.305 ;
     RECT  2.16 19.575 12.96 19.845 ;
     RECT  2.16 20.115 12.96 20.385 ;
     RECT  2.16 20.655 12.96 20.925 ;
     RECT  2.16 21.195 12.96 21.465 ;
     RECT  2.16 21.735 12.96 22.005 ;
     RECT  2.16 22.275 12.96 22.545 ;
     RECT  2.16 22.815 12.96 23.085 ;
     RECT  2.16 23.355 12.96 23.625 ;
     RECT  2.16 23.895 12.96 24.165 ;
     RECT  2.16 24.435 12.96 24.705 ;
     RECT  2.16 24.975 12.96 25.245 ;
     RECT  2.16 25.515 12.96 25.785 ;
     RECT  2.16 26.055 12.96 26.325 ;
     RECT  2.16 26.595 12.96 26.865 ;
     RECT  2.16 27.135 12.96 27.405 ;
     RECT  2.16 27.675 12.96 27.945 ;
     RECT  2.16 28.215 12.96 28.485 ;
     RECT  2.16 28.755 12.96 29.025 ;
     RECT  2.16 29.295 12.96 29.565 ;
     RECT  2.16 29.835 12.96 30.105 ;
     RECT  2.16 30.375 12.96 30.645 ;
     RECT  2.16 30.915 12.96 31.185 ;
     RECT  2.16 31.455 12.96 31.725 ;
     RECT  2.16 31.995 12.96 32.265 ;
     RECT  2.16 32.535 12.96 32.805 ;
     RECT  2.16 33.075 12.96 33.345 ;
     RECT  2.16 33.615 12.96 33.885 ;
     RECT  2.16 34.155 12.96 34.425 ;
     RECT  2.16 34.695 12.96 34.965 ;
     RECT  2.16 35.235 12.96 35.505 ;
     RECT  2.16 35.775 12.96 36.045 ;
     RECT  2.16 36.315 12.96 36.585 ;
     RECT  2.16 36.855 12.96 37.125 ;
     RECT  2.16 37.395 12.96 37.665 ;
     RECT  2.16 37.935 12.96 38.205 ;
     RECT  2.16 38.475 12.96 38.745 ;
     RECT  2.16 39.015 12.96 39.285 ;
     RECT  2.16 39.555 12.96 39.825 ;
     RECT  2.16 40.095 12.96 40.365 ;
     RECT  2.16 40.635 12.96 40.905 ;
     RECT  2.16 41.175 12.96 41.445 ;
     RECT  2.16 41.715 12.96 41.985 ;
     RECT  2.16 42.255 12.96 42.525 ;
     RECT  2.16 42.795 12.96 43.065 ;
     RECT  2.16 43.335 12.96 43.605 ;
     RECT  2.16 43.875 12.96 44.145 ;
     RECT  2.16 44.415 12.96 44.685 ;
     RECT  2.16 44.955 12.96 45.225 ;
     RECT  2.16 45.495 12.96 45.765 ;
     RECT  2.16 46.035 12.96 46.305 ;
     RECT  2.16 46.575 12.96 46.845 ;
     RECT  2.16 47.115 12.96 47.385 ;
     RECT  2.16 47.655 12.96 47.925 ;
     RECT  2.16 48.195 12.96 48.465 ;
     RECT  2.16 48.735 12.96 49.005 ;
     RECT  2.16 49.275 12.96 49.545 ;
     RECT  2.16 49.815 12.96 50.085 ;
     RECT  2.16 50.355 12.96 50.625 ;
     RECT  2.16 50.895 12.96 51.165 ;
     RECT  2.16 51.435 12.96 51.705 ;
     RECT  2.16 51.975 12.96 52.245 ;
     RECT  2.16 52.515 12.96 52.785 ;
     RECT  2.16 53.055 12.96 53.325 ;
     RECT  2.16 53.595 12.96 53.865 ;
     RECT  2.16 54.135 12.96 54.405 ;
     RECT  2.16 54.675 12.96 54.945 ;
     RECT  2.16 55.215 12.96 55.485 ;
     RECT  2.16 55.755 12.96 56.025 ;
     RECT  2.16 56.295 12.96 56.565 ;
     RECT  2.16 56.835 12.96 57.105 ;
     RECT  2.16 57.375 12.96 57.645 ;
     RECT  2.16 57.915 12.96 58.185 ;
     RECT  2.16 58.455 12.96 58.725 ;
     RECT  2.16 58.995 12.96 59.265 ;
     RECT  2.16 59.535 12.96 59.805 ;
     RECT  2.16 60.075 12.96 60.345 ;
     RECT  2.16 60.615 12.96 60.885 ;
     RECT  2.16 61.155 12.96 61.425 ;
     RECT  2.16 61.695 12.96 61.965 ;
     RECT  2.16 62.235 12.96 62.505 ;
    LAYER M1 ;
     RECT  2.16 2.151 12.96 62.649 ;
    LAYER M2 ;
     RECT  0.139 22.212 2.16 22.23 ;
     RECT  0.139 27.882 2.16 27.9 ;
     RECT  2.16 2.151 12.96 62.649 ;
     RECT  12.96 42.966 13.559 45.414 ;
     RECT  12.96 6.246 13.667 21.654 ;
     RECT  12.96 22.446 13.667 32.49 ;
     RECT  12.96 33.246 13.667 42.174 ;
     RECT  13.559 42.966 13.667 44.604 ;
     RECT  13.559 45.396 13.667 45.414 ;
     RECT  12.96 46.35 13.667 58.104 ;
     RECT  13.667 33.246 13.703 39.24 ;
     RECT  13.703 35.046 13.811 38.394 ;
     RECT  13.667 48.78 13.955 49.914 ;
     RECT  13.667 50.796 14.207 54.594 ;
     RECT  12.96 4.806 14.243 5.364 ;
     RECT  13.667 6.246 14.243 8.424 ;
     RECT  13.667 9.216 14.243 9.684 ;
     RECT  13.667 12.456 14.243 15.444 ;
     RECT  13.667 16.236 14.243 18.792 ;
     RECT  13.667 20.016 14.243 21.654 ;
     RECT  13.667 22.446 14.243 27.774 ;
     RECT  13.667 28.926 14.243 31.104 ;
     RECT  13.667 31.896 14.243 32.49 ;
     RECT  13.703 33.246 14.243 33.912 ;
     RECT  13.811 35.676 14.243 38.394 ;
     RECT  13.703 39.222 14.243 39.24 ;
     RECT  13.667 40.266 14.243 42.174 ;
     RECT  13.667 43.236 14.243 44.604 ;
     RECT  13.667 46.476 14.243 47.754 ;
     RECT  13.955 48.978 14.243 49.914 ;
     RECT  14.207 51.066 14.243 54.594 ;
     RECT  13.667 55.53 14.243 55.746 ;
     RECT  13.667 56.646 14.243 58.104 ;
     RECT  12.96 58.896 14.243 58.914 ;
     RECT  14.243 6.246 14.279 6.804 ;
     RECT  14.243 9.324 14.279 9.684 ;
     RECT  13.667 10.674 14.279 11.394 ;
     RECT  14.243 13.536 14.279 13.554 ;
     RECT  14.243 27.648 14.279 27.774 ;
     RECT  14.243 30.996 14.279 31.104 ;
     RECT  14.243 42.156 14.279 42.174 ;
     RECT  14.243 46.818 14.279 47.304 ;
     RECT  14.243 55.728 14.279 55.746 ;
     RECT  14.243 4.806 14.315 5.184 ;
     RECT  14.279 6.786 14.315 6.804 ;
     RECT  14.279 27.756 14.315 27.774 ;
     RECT  14.315 4.806 14.927 5.094 ;
     RECT  14.243 18.126 14.927 18.792 ;
     RECT  12.96 59.706 14.927 60.264 ;
     RECT  14.927 5.076 14.963 5.094 ;
     RECT  14.279 9.666 14.963 9.684 ;
     RECT  14.279 11.376 14.963 11.394 ;
     RECT  14.243 12.456 14.963 12.474 ;
     RECT  14.243 17.082 14.963 17.1 ;
     RECT  14.927 18.306 14.963 18.792 ;
     RECT  14.243 20.556 14.963 20.574 ;
     RECT  14.243 21.636 14.963 21.654 ;
     RECT  14.243 23.436 14.963 23.454 ;
     RECT  14.243 29.61 14.963 29.628 ;
     RECT  14.243 31.896 14.963 32.454 ;
     RECT  14.243 36.63 14.963 36.648 ;
     RECT  14.279 47.286 14.963 47.304 ;
     RECT  14.243 52.416 14.963 52.434 ;
     RECT  14.927 59.706 14.963 59.724 ;
    LAYER M3 ;
     RECT  2.415 2.143 2.505 2.413 ;
     RECT  5.115 2.143 5.205 2.413 ;
     RECT  7.815 2.143 7.905 2.413 ;
     RECT  10.515 2.143 10.605 2.413 ;
     RECT  7.815 2.413 8.097 4.351 ;
     RECT  6.948 4.351 8.097 4.495 ;
     RECT  6.948 4.495 8.154 4.507 ;
     RECT  6.768 4.507 8.154 4.801 ;
     RECT  9.648 0.523 9.666 4.801 ;
     RECT  10.515 2.413 10.797 4.801 ;
     RECT  14.904 4.801 14.922 4.891 ;
     RECT  6.624 4.801 8.154 4.927 ;
     RECT  6.624 4.927 8.334 5.029 ;
     RECT  12.672 4.765 12.69 5.035 ;
     RECT  9.648 4.801 10.797 5.071 ;
     RECT  14.256 4.891 14.922 5.071 ;
     RECT  5.115 2.413 5.397 5.197 ;
     RECT  5.115 5.197 5.634 5.233 ;
     RECT  6.408 5.029 8.334 5.233 ;
     RECT  5.115 5.233 8.334 5.269 ;
     RECT  2.415 2.413 2.697 5.305 ;
     RECT  4.824 5.269 8.334 5.305 ;
     RECT  9.36 5.071 10.797 5.305 ;
     RECT  12.204 5.035 12.69 5.305 ;
     RECT  14.256 5.071 14.958 5.341 ;
     RECT  2.415 5.305 2.826 5.419 ;
     RECT  14.22 5.341 14.958 5.453 ;
     RECT  3.6 5.341 3.618 5.539 ;
     RECT  4.824 5.305 11.214 5.539 ;
     RECT  2.304 5.419 2.826 5.563 ;
     RECT  3.6 5.539 11.214 5.563 ;
     RECT  2.304 5.563 11.214 5.611 ;
     RECT  12.06 5.305 12.69 5.611 ;
     RECT  14.22 5.453 14.922 5.693 ;
     RECT  2.304 5.611 12.69 5.999 ;
     RECT  14.256 5.693 14.922 6.221 ;
     RECT  2.304 5.999 12.366 6.925 ;
     RECT  2.304 6.925 12.582 7.079 ;
     RECT  14.256 6.221 14.31 7.085 ;
     RECT  2.304 7.079 12.438 7.115 ;
     RECT  4.104 7.115 12.438 7.897 ;
     RECT  2.304 7.115 3.258 8.041 ;
     RECT  4.068 7.897 12.438 8.041 ;
     RECT  14.22 7.291 14.238 8.107 ;
     RECT  2.304 8.041 12.438 8.545 ;
     RECT  2.304 8.545 12.654 8.635 ;
     RECT  2.268 8.635 12.654 8.699 ;
     RECT  13.644 8.107 14.238 8.923 ;
     RECT  2.268 8.699 12.474 9.005 ;
     RECT  13.644 8.923 14.274 9.347 ;
     RECT  13.644 9.347 13.662 9.499 ;
     RECT  13.572 9.499 13.662 9.581 ;
     RECT  2.304 9.005 12.474 9.625 ;
     RECT  14.94 9.661 14.958 9.821 ;
     RECT  13.644 9.581 13.662 10.349 ;
     RECT  2.304 9.625 12.654 10.589 ;
     RECT  14.22 10.603 14.238 10.669 ;
     RECT  14.22 10.669 14.274 10.877 ;
     RECT  14.94 11.371 14.958 11.453 ;
     RECT  2.304 10.589 12.582 11.911 ;
     RECT  0.144 11.755 0.162 11.933 ;
     RECT  2.304 11.911 12.654 12.209 ;
     RECT  13.644 11.101 13.662 12.281 ;
     RECT  2.304 12.209 12.186 12.479 ;
     RECT  14.94 12.451 14.958 12.557 ;
     RECT  2.304 12.479 12.042 12.587 ;
     RECT  3.78 12.587 12.042 13.333 ;
     RECT  2.304 12.587 2.697 13.405 ;
     RECT  3.564 13.333 12.042 13.405 ;
     RECT  2.304 13.405 12.042 13.531 ;
     RECT  14.22 12.721 14.238 13.531 ;
     RECT  2.304 13.531 12.438 13.559 ;
     RECT  3.636 13.559 12.438 13.567 ;
     RECT  14.22 13.531 14.274 13.627 ;
     RECT  13.644 13.627 14.274 13.667 ;
     RECT  14.22 13.667 14.274 14.189 ;
     RECT  3.636 13.567 12.582 14.485 ;
     RECT  3.636 14.485 12.654 14.639 ;
     RECT  2.304 13.559 2.754 14.791 ;
     RECT  3.636 14.639 12.366 14.791 ;
     RECT  14.22 14.189 14.238 14.971 ;
     RECT  2.304 14.791 12.366 15.061 ;
     RECT  2.268 15.061 12.366 15.149 ;
     RECT  13.644 14.971 14.238 15.449 ;
     RECT  2.304 15.149 12.366 15.547 ;
     RECT  13.644 15.449 13.662 15.989 ;
     RECT  2.304 15.547 12.618 16.375 ;
     RECT  2.304 16.375 12.834 16.501 ;
     RECT  2.304 16.501 12.906 16.601 ;
     RECT  14.22 16.231 14.238 16.637 ;
     RECT  2.304 16.601 12.762 16.799 ;
     RECT  13.644 16.891 13.662 16.979 ;
     RECT  14.94 17.077 14.958 17.213 ;
     RECT  2.304 16.799 12.618 17.609 ;
     RECT  14.22 17.467 14.238 17.995 ;
     RECT  2.304 17.609 12.222 18.455 ;
     RECT  2.34 18.455 12.222 18.535 ;
     RECT  14.22 17.995 14.958 18.557 ;
     RECT  14.94 18.557 14.958 18.845 ;
     RECT  2.34 18.535 12.726 19.195 ;
     RECT  13.536 19.099 13.554 19.3 ;
     RECT  13.5 19.3 13.554 19.373 ;
     RECT  2.304 19.195 12.726 19.387 ;
     RECT  2.268 19.387 12.726 19.607 ;
     RECT  2.304 19.607 12.726 19.769 ;
     RECT  13.644 19.471 13.662 19.915 ;
     RECT  2.304 19.769 12.042 20.075 ;
     RECT  13.644 19.915 14.238 20.309 ;
     RECT  14.22 20.309 14.238 20.443 ;
     RECT  14.22 20.443 14.958 20.579 ;
     RECT  2.415 20.075 12.042 20.615 ;
     RECT  2.415 20.615 11.718 20.827 ;
     RECT  14.22 20.579 14.238 21.389 ;
     RECT  2.304 20.827 11.718 21.541 ;
     RECT  13.644 21.541 13.662 21.581 ;
     RECT  2.304 21.541 12.438 21.775 ;
     RECT  14.94 21.631 14.958 21.869 ;
     RECT  0.144 22.207 0.162 22.253 ;
     RECT  14.22 22.123 14.238 22.363 ;
     RECT  2.304 21.775 12.654 22.505 ;
     RECT  13.536 22.363 14.238 22.541 ;
     RECT  14.22 22.541 14.238 22.939 ;
     RECT  2.304 22.505 12.582 23.009 ;
     RECT  2.304 23.009 12.366 23.315 ;
     RECT  14.22 22.939 14.958 23.459 ;
     RECT  14.22 23.459 14.238 23.467 ;
     RECT  13.644 23.467 14.238 23.549 ;
     RECT  11.736 23.315 12.366 23.827 ;
     RECT  11.736 23.827 12.582 24.089 ;
     RECT  2.304 23.315 10.854 24.241 ;
     RECT  14.22 23.549 14.238 24.283 ;
     RECT  11.736 24.089 12.474 24.395 ;
     RECT  11.736 24.395 12.078 24.431 ;
     RECT  2.304 24.241 10.962 24.439 ;
     RECT  11.736 24.431 11.862 24.439 ;
     RECT  13.644 24.283 14.238 24.629 ;
     RECT  2.304 24.439 11.862 25.285 ;
     RECT  2.304 25.285 12.006 25.825 ;
     RECT  2.304 25.825 12.51 26.095 ;
     RECT  14.22 24.629 14.238 26.203 ;
     RECT  2.304 26.095 12.618 26.285 ;
     RECT  13.572 26.203 14.238 26.429 ;
     RECT  3.744 26.285 12.618 26.635 ;
     RECT  13.644 26.429 14.238 26.969 ;
     RECT  2.304 26.285 2.697 27.067 ;
     RECT  2.304 27.067 2.826 27.175 ;
     RECT  3.744 26.635 12.654 27.175 ;
     RECT  14.22 26.969 14.238 27.307 ;
     RECT  14.22 27.307 14.274 27.595 ;
     RECT  2.304 27.175 12.654 27.635 ;
     RECT  14.22 27.595 14.31 27.715 ;
     RECT  13.572 27.715 14.31 27.779 ;
     RECT  2.304 27.635 11.142 27.941 ;
     RECT  0.144 27.877 0.162 27.965 ;
     RECT  12.06 27.635 12.654 28.183 ;
     RECT  13.572 27.779 13.662 28.183 ;
     RECT  12.06 28.183 13.662 28.283 ;
     RECT  12.06 28.283 12.582 28.453 ;
     RECT  2.304 27.941 11.034 28.831 ;
     RECT  11.988 28.453 12.582 28.831 ;
     RECT  13.644 28.283 13.662 28.921 ;
     RECT  2.304 28.831 12.582 29.255 ;
     RECT  13.644 28.921 14.238 29.261 ;
     RECT  4.176 29.255 12.582 29.605 ;
     RECT  14.94 29.605 14.958 29.789 ;
     RECT  4.176 29.605 12.654 30.029 ;
     RECT  0.144 29.947 0.162 30.077 ;
     RECT  13.644 29.261 13.662 30.137 ;
     RECT  2.304 29.255 3.438 30.181 ;
     RECT  4.176 30.029 11.034 30.181 ;
     RECT  2.304 30.181 11.034 30.335 ;
     RECT  14.22 30.331 14.238 30.619 ;
     RECT  14.22 30.619 14.274 30.893 ;
     RECT  0.216 30.763 0.234 30.955 ;
     RECT  2.34 30.335 11.034 30.955 ;
     RECT  11.772 30.029 12.582 30.955 ;
     RECT  0.036 30.955 0.234 30.989 ;
     RECT  0.036 30.989 0.054 31.085 ;
     RECT  2.34 30.955 12.582 31.117 ;
     RECT  2.304 31.117 12.582 31.144 ;
     RECT  2.304 31.144 13.086 31.181 ;
     RECT  2.304 31.181 12.654 31.379 ;
     RECT  14.256 30.893 14.274 31.469 ;
     RECT  13.644 31.621 13.662 32.297 ;
     RECT  14.94 31.891 14.958 32.467 ;
     RECT  2.304 31.379 12.294 32.539 ;
     RECT  14.22 32.467 14.958 32.573 ;
     RECT  2.304 32.539 12.618 32.575 ;
     RECT  2.304 32.575 12.654 32.999 ;
     RECT  14.22 32.573 14.238 33.583 ;
     RECT  13.644 33.583 14.238 33.917 ;
     RECT  2.304 32.999 12.438 33.925 ;
     RECT  13.644 33.917 13.698 34.459 ;
     RECT  2.304 33.925 12.618 34.529 ;
     RECT  0.144 34.843 0.162 34.973 ;
     RECT  13.572 34.459 13.698 34.987 ;
     RECT  13.572 34.987 13.806 35.275 ;
     RECT  2.304 34.529 12.474 35.311 ;
     RECT  13.536 35.275 13.806 35.515 ;
     RECT  13.536 35.515 14.238 35.537 ;
     RECT  2.304 35.311 12.546 35.779 ;
     RECT  14.22 35.537 14.238 36.125 ;
     RECT  2.304 35.779 13.086 36.379 ;
     RECT  2.304 36.379 13.662 36.509 ;
     RECT  14.94 36.616 14.958 36.653 ;
     RECT  13.536 36.509 13.662 36.689 ;
     RECT  13.644 36.689 13.662 36.941 ;
     RECT  2.304 36.509 12.654 37.589 ;
     RECT  14.22 37.195 14.238 38.299 ;
     RECT  13.644 38.299 14.238 38.399 ;
     RECT  2.304 37.589 12.618 38.515 ;
     RECT  2.304 38.515 12.654 38.669 ;
     RECT  0.144 38.779 0.162 38.909 ;
     RECT  13.644 38.399 13.698 39.217 ;
     RECT  2.304 38.669 12.474 39.721 ;
     RECT  0.144 39.691 0.162 39.821 ;
     RECT  13.644 39.217 14.238 39.893 ;
     RECT  2.304 39.721 12.51 40.171 ;
     RECT  2.304 40.171 12.654 40.559 ;
     RECT  2.304 40.559 12.51 40.937 ;
     RECT  14.22 39.893 14.238 41.035 ;
     RECT  2.412 40.937 12.51 41.485 ;
     RECT  0.144 41.419 0.162 41.549 ;
     RECT  2.412 41.485 12.654 41.639 ;
     RECT  2.412 41.639 12.582 41.917 ;
     RECT  13.644 41.035 14.238 42.125 ;
     RECT  13.752 42.125 14.238 42.151 ;
     RECT  13.752 42.151 14.274 42.413 ;
     RECT  2.304 41.917 12.582 42.449 ;
     RECT  2.304 42.449 12.474 42.719 ;
     RECT  13.752 42.413 13.77 42.952 ;
     RECT  13.644 42.952 13.77 42.989 ;
     RECT  2.304 42.719 12.186 43.501 ;
     RECT  14.22 43.195 14.238 43.879 ;
     RECT  2.304 43.501 12.33 43.951 ;
     RECT  13.536 43.879 14.238 44.333 ;
     RECT  14.22 44.333 14.238 44.621 ;
     RECT  2.304 43.951 12.582 44.915 ;
     RECT  13.536 45.115 13.554 45.329 ;
     RECT  2.304 44.915 8.874 45.805 ;
     RECT  2.304 45.805 8.91 46.201 ;
     RECT  9.684 44.915 12.582 46.201 ;
     RECT  2.304 46.201 12.582 46.219 ;
     RECT  13.644 45.391 13.662 46.219 ;
     RECT  2.304 46.219 13.662 46.373 ;
     RECT  2.304 46.373 13.086 46.607 ;
     RECT  14.22 46.471 14.238 46.813 ;
     RECT  14.22 46.813 14.274 46.829 ;
     RECT  2.304 46.607 12.726 47.039 ;
     RECT  0.144 46.171 0.162 47.117 ;
     RECT  14.256 46.829 14.274 47.281 ;
     RECT  14.256 47.281 14.958 47.357 ;
     RECT  2.304 47.039 12.618 47.849 ;
     RECT  13.644 47.611 14.238 47.885 ;
     RECT  2.304 47.849 12.438 48.119 ;
     RECT  13.644 47.885 13.662 48.715 ;
     RECT  13.644 48.715 13.95 48.731 ;
     RECT  13.932 48.731 13.95 48.803 ;
     RECT  2.304 48.119 12.186 48.901 ;
     RECT  2.304 48.901 12.618 49.001 ;
     RECT  14.22 48.955 14.238 49.531 ;
     RECT  2.304 49.001 12.546 49.855 ;
     RECT  2.304 49.855 12.618 50.009 ;
     RECT  13.644 49.531 14.238 50.381 ;
     RECT  2.304 50.009 12.474 50.549 ;
     RECT  14.184 50.381 14.238 51.163 ;
     RECT  2.304 50.549 11.934 51.331 ;
     RECT  2.304 51.331 12.078 51.395 ;
     RECT  11.52 51.395 12.078 51.511 ;
     RECT  13.644 51.163 14.238 51.899 ;
     RECT  11.52 51.511 12.582 52.015 ;
     RECT  11.52 52.015 12.618 52.213 ;
     RECT  13.644 51.899 13.662 52.213 ;
     RECT  2.304 51.395 10.797 52.285 ;
     RECT  11.52 52.213 13.662 52.285 ;
     RECT  2.304 52.285 13.662 52.301 ;
     RECT  13.644 52.301 13.662 52.349 ;
     RECT  14.94 52.411 14.958 52.541 ;
     RECT  14.22 52.789 14.238 53.083 ;
     RECT  13.644 53.083 14.238 53.321 ;
     RECT  2.304 52.301 12.402 53.491 ;
     RECT  2.304 53.491 12.618 53.519 ;
     RECT  12.384 53.519 12.618 53.789 ;
     RECT  12.384 53.789 12.402 53.861 ;
     RECT  14.22 53.321 14.238 54.187 ;
     RECT  2.304 53.519 11.646 54.239 ;
     RECT  9.684 54.239 11.646 54.301 ;
     RECT  9.684 54.301 11.754 54.841 ;
     RECT  13.644 54.187 14.238 54.869 ;
     RECT  9.684 54.841 12.114 54.877 ;
     RECT  9.684 54.877 12.438 54.985 ;
     RECT  14.22 54.869 14.238 55.003 ;
     RECT  2.304 54.239 8.946 55.021 ;
     RECT  9.684 54.985 12.654 55.021 ;
     RECT  2.304 55.021 12.654 55.099 ;
     RECT  2.268 55.099 12.654 55.247 ;
     RECT  2.304 55.247 12.654 55.381 ;
     RECT  14.22 55.003 14.274 55.751 ;
     RECT  2.304 55.381 13.122 55.853 ;
     RECT  2.304 55.853 12.654 55.949 ;
     RECT  2.304 55.949 12.618 56.155 ;
     RECT  13.644 56.107 13.662 56.632 ;
     RECT  2.268 56.155 12.618 56.759 ;
     RECT  2.268 56.759 12.474 57.029 ;
     RECT  2.268 57.029 12.402 57.065 ;
     RECT  13.644 56.632 14.238 57.839 ;
     RECT  2.304 57.065 12.402 58.109 ;
     RECT  2.304 58.109 11.718 58.145 ;
     RECT  2.304 58.145 11.61 58.363 ;
     RECT  2.268 58.363 11.61 58.487 ;
     RECT  12.528 58.351 12.618 58.531 ;
     RECT  14.22 57.839 14.238 58.555 ;
     RECT  12.528 58.531 12.834 58.649 ;
     RECT  14.22 58.555 14.958 58.919 ;
     RECT  12.528 58.649 12.654 59.071 ;
     RECT  2.304 58.487 11.61 59.161 ;
     RECT  12.456 59.071 12.654 59.161 ;
     RECT  2.304 59.161 12.654 59.261 ;
     RECT  7.308 59.261 12.654 59.459 ;
     RECT  2.304 59.261 4.086 59.495 ;
     RECT  9.684 59.459 12.654 59.495 ;
     RECT  4.824 59.261 6.282 59.531 ;
     RECT  7.308 59.459 8.838 59.531 ;
     RECT  4.932 59.531 6.282 59.567 ;
     RECT  2.304 59.495 4.014 59.639 ;
     RECT  4.932 59.567 6.174 59.729 ;
     RECT  7.308 59.531 8.334 59.729 ;
     RECT  9.684 59.495 10.797 59.729 ;
     RECT  14.868 58.919 14.958 59.729 ;
     RECT  2.415 59.639 4.014 59.765 ;
     RECT  6.156 59.729 6.174 59.765 ;
     RECT  10.116 59.729 10.797 59.765 ;
     RECT  3.996 59.765 4.014 59.801 ;
     RECT  4.932 59.729 5.397 59.801 ;
     RECT  11.556 59.495 12.654 59.801 ;
     RECT  13.608 59.371 13.626 59.837 ;
     RECT  7.416 59.729 8.334 59.999 ;
     RECT  11.808 59.801 12.654 59.999 ;
     RECT  14.868 59.729 14.922 59.999 ;
     RECT  7.416 59.999 8.097 60.035 ;
     RECT  11.808 59.999 11.826 60.035 ;
     RECT  12.6 59.999 12.654 60.035 ;
     RECT  14.904 59.999 14.922 60.269 ;
     RECT  12.636 60.035 12.654 60.305 ;
     RECT  2.415 59.765 2.697 62.387 ;
     RECT  5.115 59.801 5.397 62.387 ;
     RECT  7.815 60.035 8.097 62.387 ;
     RECT  10.515 59.765 10.797 62.387 ;
     RECT  2.415 62.387 2.505 62.657 ;
     RECT  5.115 62.387 5.205 62.657 ;
     RECT  7.815 62.387 7.905 62.657 ;
     RECT  10.515 62.387 10.605 62.657 ;
    LAYER M4 ;
     RECT  0.085 1.392 0.108 1.416 ;
     RECT  0.108 5.424 2.408 59.4 ;
     RECT  2.408 2.148 2.512 62.652 ;
     RECT  2.512 2.418 2.704 62.382 ;
     RECT  2.704 7.2 2.765 9.816 ;
     RECT  2.704 13.92 2.765 15.336 ;
     RECT  2.704 30.048 2.765 33.624 ;
     RECT  2.704 39.792 2.765 43.368 ;
     RECT  2.704 50.976 2.765 52.296 ;
     RECT  2.704 53.52 2.765 53.592 ;
     RECT  2.704 56.544 2.765 56.568 ;
     RECT  2.765 14.496 2.801 15.336 ;
     RECT  2.704 20.4 2.837 27.72 ;
     RECT  2.765 30.048 2.837 31.992 ;
     RECT  2.765 33.024 2.837 33.624 ;
     RECT  2.765 39.792 2.837 42.312 ;
     RECT  2.837 25.008 2.867 26.232 ;
     RECT  2.765 7.2 2.873 7.656 ;
     RECT  2.837 39.792 2.873 40.344 ;
     RECT  2.704 45.552 2.873 47.784 ;
     RECT  2.765 52.272 2.873 52.296 ;
     RECT  2.704 11.76 3.017 12.552 ;
     RECT  2.837 20.4 3.017 24.024 ;
     RECT  2.837 30.048 3.017 31.368 ;
     RECT  2.704 36.432 3.017 38.808 ;
     RECT  2.704 59.184 3.017 59.208 ;
     RECT  2.704 16.368 3.305 18.744 ;
     RECT  2.704 48.768 3.34 48.792 ;
     RECT  2.837 41.424 3.347 42.312 ;
     RECT  2.765 8.976 3.395 9.816 ;
     RECT  3.017 30.48 3.395 31.368 ;
     RECT  3.017 36.432 3.443 38.232 ;
     RECT  3.395 9.792 3.449 9.816 ;
     RECT  3.305 16.512 3.485 18.744 ;
     RECT  2.704 34.944 3.557 34.968 ;
     RECT  2.704 5.568 3.685 5.592 ;
     RECT  3.685 5.568 3.772 6.312 ;
     RECT  3.485 18 3.836 18.744 ;
     RECT  3.017 11.952 3.841 12.552 ;
     RECT  3.836 18 3.877 19.176 ;
     RECT  3.017 20.4 3.877 22.344 ;
     RECT  2.867 25.008 3.877 26.136 ;
     RECT  3.443 36.48 3.881 38.232 ;
     RECT  3.347 41.424 3.913 41.64 ;
     RECT  3.395 30.864 3.925 31.368 ;
     RECT  2.873 39.792 3.949 39.912 ;
     RECT  3.913 40.992 3.949 41.64 ;
     RECT  2.704 44.448 3.949 44.472 ;
     RECT  2.873 45.552 3.949 46.296 ;
     RECT  3.841 11.952 3.953 13.08 ;
     RECT  3.017 23.328 3.971 24.024 ;
     RECT  3.949 44.448 4.021 46.296 ;
     RECT  2.765 53.568 4.057 53.592 ;
     RECT  2.704 54.96 4.057 54.984 ;
     RECT  2.801 14.496 4.093 14.952 ;
     RECT  2.873 7.632 4.237 7.656 ;
     RECT  3.925 30.864 4.381 32.04 ;
     RECT  2.837 33.024 4.381 33.048 ;
     RECT  2.873 47.76 4.453 47.784 ;
     RECT  3.877 18 4.489 22.344 ;
     RECT  3.971 23.328 4.489 23.544 ;
     RECT  4.453 47.28 4.489 47.784 ;
     RECT  4.237 7.632 4.525 8.52 ;
     RECT  4.525 7.632 4.597 8.856 ;
     RECT  4.597 7.632 4.741 9.192 ;
     RECT  3.877 25.008 4.777 26.28 ;
     RECT  4.777 10.608 4.813 10.632 ;
     RECT  3.949 27.312 4.844 27.336 ;
     RECT  3.881 36.48 4.844 37.896 ;
     RECT  3.949 39.216 4.844 41.64 ;
     RECT  3.953 13.056 4.849 13.08 ;
     RECT  4.093 14.4 4.849 14.952 ;
     RECT  4.501 52.272 4.885 52.296 ;
     RECT  2.765 43.344 4.981 43.368 ;
     RECT  4.844 27.312 4.993 27.912 ;
     RECT  4.741 7.632 5.065 9.576 ;
     RECT  4.813 10.608 5.065 10.92 ;
     RECT  4.993 27.312 5.065 28.248 ;
     RECT  4.844 29.376 5.065 29.4 ;
     RECT  2.765 50.976 5.065 51 ;
     RECT  3.485 16.512 5.101 16.536 ;
     RECT  3.772 5.568 5.108 5.592 ;
     RECT  5.065 7.632 5.108 10.92 ;
     RECT  3.953 11.952 5.108 12.024 ;
     RECT  4.849 13.056 5.108 14.952 ;
     RECT  5.101 15.984 5.108 16.536 ;
     RECT  4.489 18 5.108 23.544 ;
     RECT  4.777 25.008 5.108 26.328 ;
     RECT  5.065 27.312 5.108 29.88 ;
     RECT  4.381 30.864 5.108 33.048 ;
     RECT  5.065 34.752 5.108 34.776 ;
     RECT  4.844 36.48 5.108 41.64 ;
     RECT  4.981 42.72 5.108 43.368 ;
     RECT  4.021 44.352 5.108 46.296 ;
     RECT  4.489 47.28 5.108 48.456 ;
     RECT  5.065 50.928 5.108 51 ;
     RECT  4.885 52.272 5.108 52.344 ;
     RECT  4.057 53.568 5.108 54.984 ;
     RECT  5.108 2.148 5.212 62.652 ;
     RECT  5.212 2.418 5.404 62.382 ;
     RECT  5.404 5.04 6.293 47.304 ;
     RECT  5.404 59.184 6.293 59.256 ;
     RECT  5.404 57.504 6.433 57.816 ;
     RECT  6.293 5.04 6.757 29.112 ;
     RECT  6.293 30.096 6.793 47.304 ;
     RECT  5.404 48.288 6.793 55.944 ;
     RECT  6.433 57.504 6.901 58.152 ;
     RECT  6.293 59.184 6.901 59.208 ;
     RECT  6.901 57.504 7.225 59.208 ;
     RECT  6.793 30.096 7.261 55.944 ;
     RECT  7.261 30.096 7.297 56.376 ;
     RECT  7.225 57.408 7.297 59.208 ;
     RECT  7.297 30.096 7.477 59.208 ;
     RECT  6.757 4.512 7.549 29.112 ;
     RECT  7.477 30.096 7.549 59.304 ;
     RECT  7.549 4.512 7.808 59.304 ;
     RECT  7.808 2.148 7.912 62.652 ;
     RECT  7.912 2.418 8.104 62.382 ;
     RECT  8.104 54.72 8.165 56.52 ;
     RECT  8.104 47.952 8.237 53.592 ;
     RECT  8.165 56.352 8.237 56.52 ;
     RECT  8.104 9.072 8.273 44.472 ;
     RECT  8.104 5.76 8.309 7.992 ;
     RECT  8.237 48.384 8.309 53.592 ;
     RECT  8.309 51.696 8.345 53.592 ;
     RECT  8.237 56.352 8.381 56.376 ;
     RECT  8.273 9.072 8.425 30.6 ;
     RECT  8.425 9.072 8.453 26.808 ;
     RECT  8.273 31.68 8.561 44.472 ;
     RECT  8.453 9.072 8.597 15.288 ;
     RECT  8.309 48.384 8.597 50.664 ;
     RECT  8.165 54.72 8.633 55.272 ;
     RECT  8.561 34.752 8.64 44.472 ;
     RECT  8.64 39.744 8.675 44.472 ;
     RECT  8.309 5.856 8.777 7.992 ;
     RECT  8.345 51.84 8.813 53.592 ;
     RECT  8.597 9.12 8.819 15.288 ;
     RECT  8.64 34.752 8.819 38.52 ;
     RECT  8.777 5.856 8.841 7.416 ;
     RECT  8.453 16.464 8.849 26.808 ;
     RECT  8.425 27.888 8.849 30.6 ;
     RECT  8.675 39.744 8.849 43.752 ;
     RECT  8.597 50.64 8.849 50.664 ;
     RECT  8.813 53.376 8.849 53.592 ;
     RECT  8.841 5.856 8.86 5.88 ;
     RECT  8.819 36.336 8.867 38.52 ;
     RECT  8.819 9.552 8.885 15.288 ;
     RECT  8.849 29.04 8.885 30.6 ;
     RECT  8.104 57.504 8.893 59.304 ;
     RECT  8.849 39.744 8.915 42.216 ;
     RECT  8.885 30.096 8.921 30.6 ;
     RECT  8.813 51.84 8.921 52.392 ;
     RECT  8.561 31.68 8.957 33.576 ;
     RECT  8.597 48.384 8.957 49.512 ;
     RECT  8.849 27.888 9.059 27.912 ;
     RECT  8.849 16.464 9.065 26.28 ;
     RECT  8.867 36.336 9.065 36.936 ;
     RECT  9.065 16.464 9.101 22.872 ;
     RECT  9.101 16.56 9.107 22.872 ;
     RECT  9.107 16.56 9.137 19.704 ;
     RECT  8.915 39.744 9.173 42.168 ;
     RECT  8.885 10.032 9.209 15.288 ;
     RECT  9.209 13.536 9.245 15.288 ;
     RECT  8.885 29.04 9.245 29.064 ;
     RECT  8.867 38.112 9.245 38.52 ;
     RECT  9.065 36.432 9.281 36.936 ;
     RECT  8.921 30.384 9.317 30.6 ;
     RECT  9.317 30.576 9.353 30.6 ;
     RECT  9.107 20.88 9.389 22.872 ;
     RECT  9.065 23.904 9.425 26.28 ;
     RECT  8.957 31.68 9.425 33.096 ;
     RECT  8.849 43.488 9.425 43.752 ;
     RECT  8.921 51.84 9.461 51.864 ;
     RECT  8.849 53.376 9.461 53.4 ;
     RECT  9.425 31.968 9.497 33.096 ;
     RECT  9.637 0.528 9.731 0.552 ;
     RECT  8.633 54.72 9.836 54.744 ;
     RECT  8.104 45.552 9.877 46.68 ;
     RECT  9.745 50.304 9.877 50.328 ;
     RECT  9.173 39.888 9.889 42.168 ;
     RECT  9.425 43.488 9.889 43.608 ;
     RECT  9.932 6.144 9.973 6.168 ;
     RECT  9.877 45.552 10.028 47.064 ;
     RECT  8.893 57.504 10.105 58.488 ;
     RECT  9.137 17.472 10.177 19.704 ;
     RECT  9.245 14.112 10.261 15.096 ;
     RECT  10.177 17.088 10.261 19.704 ;
     RECT  10.028 44.976 10.357 47.064 ;
     RECT  8.957 48.384 10.357 49.32 ;
     RECT  9.877 50.304 10.357 50.664 ;
     RECT  9.836 53.136 10.357 53.16 ;
     RECT  9.836 54.144 10.357 54.744 ;
     RECT  9.973 5.616 10.508 6.168 ;
     RECT  8.841 7.2 10.508 7.416 ;
     RECT  9.853 8.496 10.508 8.52 ;
     RECT  9.209 10.032 10.508 12.312 ;
     RECT  10.261 14.112 10.508 15.48 ;
     RECT  10.261 16.56 10.508 19.704 ;
     RECT  9.389 20.88 10.508 22.776 ;
     RECT  9.425 23.904 10.508 24.408 ;
     RECT  9.425 25.44 10.508 26.28 ;
     RECT  9.781 27.312 10.508 27.336 ;
     RECT  10.165 28.752 10.508 28.776 ;
     RECT  9.497 32.064 10.508 33.096 ;
     RECT  8.819 34.752 10.508 34.776 ;
     RECT  9.281 36.432 10.508 36.456 ;
     RECT  9.245 38.16 10.508 38.52 ;
     RECT  9.889 39.888 10.508 43.608 ;
     RECT  10.357 44.976 10.508 47.16 ;
     RECT  10.357 48.384 10.508 50.664 ;
     RECT  9.529 51.792 10.508 51.816 ;
     RECT  10.357 53.04 10.508 53.16 ;
     RECT  10.357 54.144 10.508 54.84 ;
     RECT  10.105 57.504 10.508 58.728 ;
     RECT  10.508 2.148 10.612 62.652 ;
     RECT  10.612 2.418 10.804 62.382 ;
     RECT  10.804 19.008 10.865 19.032 ;
     RECT  10.804 12.288 10.901 12.312 ;
     RECT  10.804 40.848 10.931 42.792 ;
     RECT  10.804 47.136 10.931 47.16 ;
     RECT  10.804 54.72 10.931 54.984 ;
     RECT  10.804 57.6 10.931 58.152 ;
     RECT  10.931 40.848 10.937 40.872 ;
     RECT  10.931 58.128 10.937 58.152 ;
     RECT  10.931 41.952 10.973 41.976 ;
     RECT  10.931 54.96 10.973 54.984 ;
     RECT  10.804 56.016 10.973 56.04 ;
     RECT  10.804 17.472 11.009 17.496 ;
     RECT  10.804 45.024 11.009 45.048 ;
     RECT  10.804 46.08 11.081 46.104 ;
     RECT  10.804 52.416 12.305 52.44 ;
     RECT  12.193 45.696 12.553 45.72 ;
     RECT  12.553 44.88 13.057 45.72 ;
     RECT  12.589 55.296 13.093 55.32 ;
     RECT  13.489 19.344 13.525 19.368 ;
     RECT  13.057 35.808 13.525 35.832 ;
     RECT  13.057 44.88 13.525 46.248 ;
     RECT  12.553 28.128 13.561 28.152 ;
     RECT  13.525 35.28 13.561 36.408 ;
     RECT  13.561 9.504 13.633 9.528 ;
     RECT  12.373 11.952 13.633 11.976 ;
     RECT  12.589 15.552 13.633 16.104 ;
     RECT  13.525 19.104 13.633 19.368 ;
     RECT  13.525 22.368 13.633 22.392 ;
     RECT  13.561 26.208 13.633 26.232 ;
     RECT  13.561 27.888 13.633 28.152 ;
     RECT  13.057 31.152 13.633 31.176 ;
     RECT  13.561 34.464 13.633 36.408 ;
     RECT  10.804 37.44 13.633 37.464 ;
     RECT  12.589 40.224 13.633 40.248 ;
     RECT  13.525 44.304 13.633 46.248 ;
     RECT  12.517 49.776 13.633 49.8 ;
     RECT  13.057 52.272 13.633 52.296 ;
     RECT  13.093 55.296 13.633 55.848 ;
     RECT  13.633 47.616 13.921 48.456 ;
     RECT  13.633 49.536 13.921 53.112 ;
     RECT  13.633 8.112 14.209 8.136 ;
     RECT  13.633 9.216 14.209 12.264 ;
     RECT  13.633 13.632 14.209 13.656 ;
     RECT  13.633 14.976 14.209 16.92 ;
     RECT  13.633 19.104 14.209 20.232 ;
     RECT  13.633 21.552 14.209 22.392 ;
     RECT  13.633 23.472 14.209 24.6 ;
     RECT  13.633 26.208 14.209 26.808 ;
     RECT  13.633 27.888 14.209 30.072 ;
     RECT  13.633 31.152 14.209 32.28 ;
     RECT  13.633 33.6 14.209 42.984 ;
     RECT  13.633 44.016 14.209 46.248 ;
     RECT  13.921 47.616 14.209 53.112 ;
     RECT  13.633 54.192 14.209 57.768 ;
     RECT  14.209 5.664 14.245 5.688 ;
     RECT  14.209 7.296 14.245 58.296 ;
     RECT  14.245 5.664 14.857 58.296 ;
     RECT  13.597 59.376 14.857 59.4 ;
     RECT  14.857 5.664 14.929 59.4 ;
     RECT  14.929 5.424 15.036 59.4 ;
    LAYER M5 ;
     RECT  0.192 1.285 0.216 1.381 ;
     RECT  0.096 1.381 0.216 1.427 ;
     RECT  2.4 2.137 2.52 2.151 ;
     RECT  5.1 2.137 5.22 2.151 ;
     RECT  7.8 2.137 7.92 2.151 ;
     RECT  10.5 2.137 10.62 2.151 ;
     RECT  5.1 2.151 5.412 5.029 ;
     RECT  5.1 5.029 6.312 5.077 ;
     RECT  10.5 2.151 10.812 5.605 ;
     RECT  7.8 2.151 8.112 5.845 ;
     RECT  5.1 5.077 6.792 6.229 ;
     RECT  7.8 5.845 8.808 6.229 ;
     RECT  5.1 6.229 8.808 6.851 ;
     RECT  5.1 6.851 8.112 7.187 ;
     RECT  5.1 7.187 6.312 7.379 ;
     RECT  9.984 5.605 10.812 7.427 ;
     RECT  3.696 5.557 3.72 7.667 ;
     RECT  5.1 7.379 6.216 8.485 ;
     RECT  10.5 7.427 10.812 8.485 ;
     RECT  2.4 2.151 2.712 8.965 ;
     RECT  7.8 7.187 8.112 9.109 ;
     RECT  2.4 8.965 3.384 9.827 ;
     RECT  9.936 8.485 10.812 10.021 ;
     RECT  5.1 8.485 6.264 10.117 ;
     RECT  7.8 9.109 8.808 10.501 ;
     RECT  9.792 10.021 10.812 10.501 ;
     RECT  5.1 10.117 6.6 11.365 ;
     RECT  7.8 10.501 10.812 11.365 ;
     RECT  5.1 11.365 10.812 13.235 ;
     RECT  9.84 13.235 10.812 14.147 ;
     RECT  5.1 13.235 8.856 14.389 ;
     RECT  2.4 9.827 2.712 14.485 ;
     RECT  5.1 14.389 8.904 14.531 ;
     RECT  5.1 14.531 8.856 14.627 ;
     RECT  2.4 14.485 3.384 14.915 ;
     RECT  10.272 14.147 10.812 17.123 ;
     RECT  5.1 14.627 8.52 19.237 ;
     RECT  3.888 19.141 3.912 19.621 ;
     RECT  3.888 19.621 4.008 19.667 ;
     RECT  5.1 19.237 9.096 20.869 ;
     RECT  10.5 17.123 10.812 20.869 ;
     RECT  5.1 20.869 10.812 21.107 ;
     RECT  5.1 21.107 8.52 21.395 ;
     RECT  3.984 19.667 4.008 21.683 ;
     RECT  5.1 21.395 5.412 22.741 ;
     RECT  4.56 22.741 5.412 23.317 ;
     RECT  6.528 21.395 8.52 23.317 ;
     RECT  3.936 23.317 8.52 23.555 ;
     RECT  5.1 23.555 8.52 23.987 ;
     RECT  3.936 23.555 3.96 24.035 ;
     RECT  5.1 23.987 5.412 24.949 ;
     RECT  6.528 23.987 8.52 24.949 ;
     RECT  2.4 14.915 2.712 25.717 ;
     RECT  2.4 25.717 2.856 26.243 ;
     RECT  9.792 21.107 10.812 27.347 ;
     RECT  5.1 24.949 8.52 27.877 ;
     RECT  10.176 27.347 10.812 28.787 ;
     RECT  2.4 26.243 2.712 30.469 ;
     RECT  0.096 1.427 0.12 30.899 ;
     RECT  4.896 27.877 9.048 30.995 ;
     RECT  2.4 30.469 3.384 31.285 ;
     RECT  2.4 31.285 3.96 31.379 ;
     RECT  3.936 31.379 3.96 32.051 ;
     RECT  5.1 30.995 9.048 32.531 ;
     RECT  5.1 32.531 8.52 34.741 ;
     RECT  2.4 31.379 2.712 36.421 ;
     RECT  5.1 34.741 8.808 36.467 ;
     RECT  5.1 36.467 8.52 37.573 ;
     RECT  2.4 36.421 3.432 37.907 ;
     RECT  2.4 37.907 2.808 38.243 ;
     RECT  4.896 37.573 8.856 38.531 ;
     RECT  4.896 38.531 8.568 39.395 ;
     RECT  4.896 39.395 5.412 39.731 ;
     RECT  10.5 28.787 10.812 39.877 ;
     RECT  6.672 39.395 8.568 40.405 ;
     RECT  9.696 39.877 10.812 40.405 ;
     RECT  6.672 40.405 10.812 40.883 ;
     RECT  5.1 39.731 5.412 40.981 ;
     RECT  10.5 40.883 10.812 41.461 ;
     RECT  2.4 38.243 2.712 41.557 ;
     RECT  3.936 40.981 3.96 41.557 ;
     RECT  2.4 41.557 3.96 41.651 ;
     RECT  5.1 40.981 5.688 41.651 ;
     RECT  6.672 40.883 9.096 41.651 ;
     RECT  10.5 41.461 10.92 42.133 ;
     RECT  6.672 41.651 8.904 42.227 ;
     RECT  2.4 41.651 3.336 42.323 ;
     RECT  5.1 41.651 5.412 42.709 ;
     RECT  4.992 42.709 5.412 43.285 ;
     RECT  6.912 42.227 8.664 43.285 ;
     RECT  4.992 43.285 8.664 43.379 ;
     RECT  5.1 43.379 8.664 44.483 ;
     RECT  5.1 44.483 8.52 44.725 ;
     RECT  10.08 42.133 10.92 45.011 ;
     RECT  10.5 45.011 10.92 45.059 ;
     RECT  4.176 44.725 8.52 45.587 ;
     RECT  4.608 45.587 8.52 45.683 ;
     RECT  4.608 45.683 5.64 45.731 ;
     RECT  10.5 45.059 10.812 46.021 ;
     RECT  9.888 46.021 10.812 46.069 ;
     RECT  9.888 46.069 10.92 47.171 ;
     RECT  2.4 42.323 2.712 47.749 ;
     RECT  4.608 45.731 5.412 48.419 ;
     RECT  2.4 47.749 3.288 48.803 ;
     RECT  5.1 48.419 5.412 50.581 ;
     RECT  6.912 45.683 8.52 50.581 ;
     RECT  5.1 50.581 8.52 51.539 ;
     RECT  5.1 51.539 5.412 52.261 ;
     RECT  4.512 52.261 5.412 53.557 ;
     RECT  4.464 53.557 5.412 54.275 ;
     RECT  5.1 54.275 5.412 54.661 ;
     RECT  9.888 47.171 10.812 54.709 ;
     RECT  9.888 54.709 10.92 54.755 ;
     RECT  10.368 54.755 10.92 54.851 ;
     RECT  5.1 54.661 5.88 55.955 ;
     RECT  10.5 54.851 10.92 57.635 ;
     RECT  6.912 51.539 8.52 58.453 ;
     RECT  6.912 58.453 8.856 58.739 ;
     RECT  7.248 58.739 8.856 58.979 ;
     RECT  7.488 58.979 8.856 59.315 ;
     RECT  2.4 48.803 2.712 62.649 ;
     RECT  5.1 55.955 5.412 62.649 ;
     RECT  7.8 59.315 8.112 62.649 ;
     RECT  10.5 57.635 10.812 62.649 ;
     RECT  2.4 62.649 2.52 62.663 ;
     RECT  5.1 62.649 5.22 62.663 ;
     RECT  7.8 62.649 7.92 62.663 ;
     RECT  10.5 62.649 10.62 62.663 ;
     RECT  6.312 5.029 7.8 5.077 ;
     RECT  6.792 5.077 7.8 6.229 ;
     RECT  2.712 5.557 3.696 7.667 ;
     RECT  3.72 5.557 5.1 7.667 ;
     RECT  8.808 5.845 9.984 6.851 ;
     RECT  6.312 7.187 7.8 7.379 ;
     RECT  6.216 7.379 6.264 8.485 ;
     RECT  9.984 7.427 10.5 8.485 ;
     RECT  2.712 7.667 3.384 8.965 ;
     RECT  8.808 9.109 9.936 10.021 ;
     RECT  8.808 10.021 9.792 10.501 ;
     RECT  6.6 10.117 7.8 11.365 ;
     RECT  8.856 13.235 9.84 14.147 ;
     RECT  8.856 14.147 10.272 14.389 ;
     RECT  8.904 14.389 10.272 14.531 ;
     RECT  8.856 14.531 10.272 14.627 ;
     RECT  2.712 19.141 3.888 19.667 ;
     RECT  3.912 19.141 5.1 19.621 ;
     RECT  9.096 19.237 10.5 20.869 ;
     RECT  4.008 19.621 5.1 21.683 ;
     RECT  2.712 19.667 3.984 21.683 ;
     RECT  8.52 21.107 9.792 27.347 ;
     RECT  5.412 21.395 6.528 23.317 ;
     RECT  4.56 21.683 5.1 22.741 ;
     RECT  2.712 23.317 3.936 24.035 ;
     RECT  3.96 23.555 5.1 24.035 ;
     RECT  5.412 23.987 6.528 24.949 ;
     RECT  8.52 27.347 10.176 27.877 ;
     RECT  9.048 27.877 10.176 28.787 ;
     RECT  9.048 28.787 10.5 32.531 ;
     RECT  3.384 30.469 4.896 30.995 ;
     RECT  3.384 30.995 5.1 31.285 ;
     RECT  3.96 31.285 5.1 32.051 ;
     RECT  2.712 31.379 3.936 32.051 ;
     RECT  8.52 36.467 8.808 37.573 ;
     RECT  3.432 37.573 4.896 37.907 ;
     RECT  8.568 38.531 8.856 39.877 ;
     RECT  5.412 39.395 6.672 40.981 ;
     RECT  4.896 39.731 5.1 40.981 ;
     RECT  8.568 39.877 9.696 40.405 ;
     RECT  9.096 40.883 10.5 41.651 ;
     RECT  2.712 40.981 3.936 41.557 ;
     RECT  3.96 40.981 5.1 41.651 ;
     RECT  5.688 40.981 6.672 41.651 ;
     RECT  4.992 41.651 5.1 42.709 ;
     RECT  5.412 41.651 6.672 42.227 ;
     RECT  8.904 41.651 10.5 42.133 ;
     RECT  8.904 42.133 10.08 42.227 ;
     RECT  5.412 42.227 6.912 43.285 ;
     RECT  8.664 42.227 10.08 44.483 ;
     RECT  4.992 43.379 5.1 44.725 ;
     RECT  2.712 44.725 4.176 45.587 ;
     RECT  10.08 45.011 10.5 46.021 ;
     RECT  10.812 45.059 10.92 46.069 ;
     RECT  5.64 45.683 6.912 45.731 ;
     RECT  5.412 45.731 6.912 50.581 ;
     RECT  8.52 46.021 9.888 54.755 ;
     RECT  3.288 47.749 4.608 48.419 ;
     RECT  5.412 51.539 6.912 54.661 ;
     RECT  5.88 54.661 6.912 55.955 ;
     RECT  5.412 55.955 6.912 58.739 ;
  END
END qwen_tx_rnes_r0
END LIBRARY
